VERSION 5.8 ;
BUSBITCHARS "[]" ;
DIVIDERCHAR "/" ;
UNITS
    DATABASE MICRONS 1000 ;
END UNITS

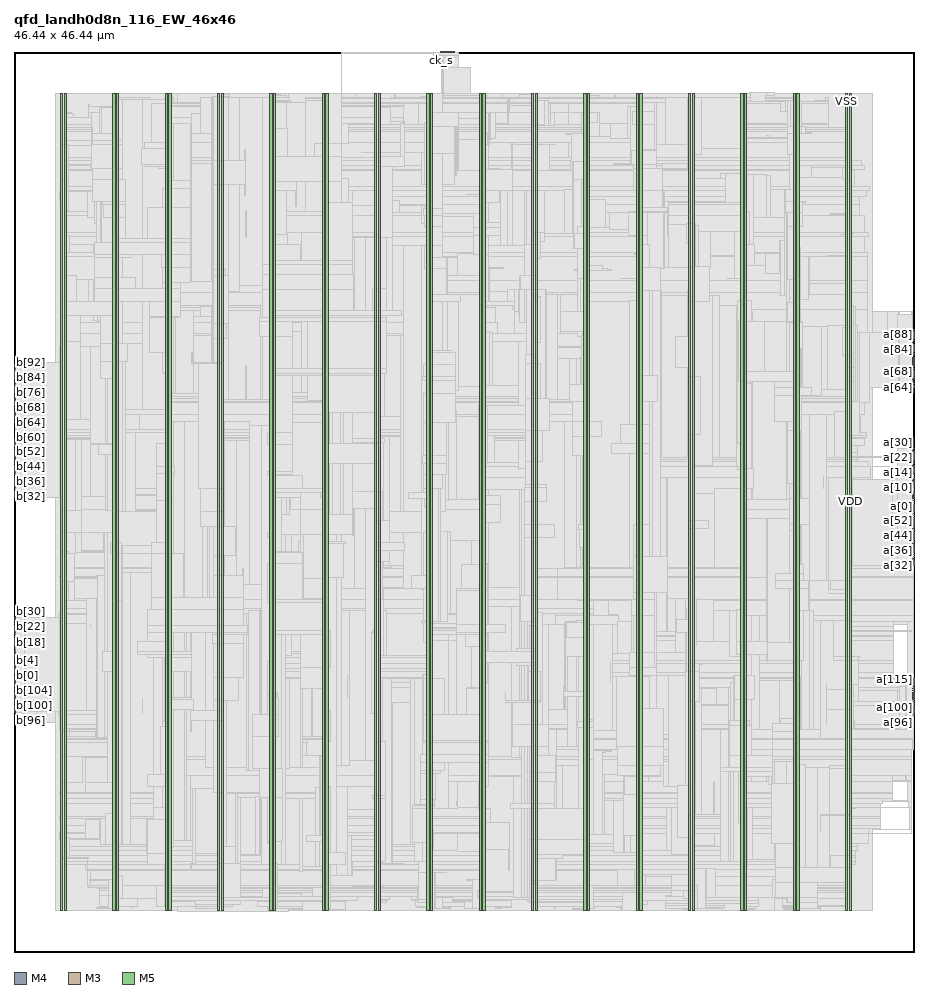
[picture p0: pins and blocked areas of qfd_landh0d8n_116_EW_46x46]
MACRO qfd_landh0d8n_116_EW_46x46
  FOREIGN qfd_landh0d8n_116_EW_46x46 0 0 ;
  CLASS BLOCK ;
  SIZE 46.44 BY 46.44 ;
  PIN a[0]
    DIRECTION INPUT ;
    USE SIGNAL ;
    PORT
      LAYER M4 ;
        RECT  46.356 22.992 46.44 23.016 ;
    END
  END a[0]
  PIN a[100]
    DIRECTION INPUT ;
    USE SIGNAL ;
    PORT
      LAYER M4 ;
        RECT  46.356 12.624 46.44 12.648 ;
    END
  END a[100]
  PIN a[101]
    DIRECTION INPUT ;
    USE SIGNAL ;
    PORT
      LAYER M4 ;
        RECT  46.356 12.72 46.44 12.744 ;
    END
  END a[101]
  PIN a[102]
    DIRECTION INPUT ;
    USE SIGNAL ;
    PORT
      LAYER M4 ;
        RECT  46.356 12.816 46.44 12.84 ;
    END
  END a[102]
  PIN a[103]
    DIRECTION INPUT ;
    USE SIGNAL ;
    PORT
      LAYER M4 ;
        RECT  46.356 12.912 46.44 12.936 ;
    END
  END a[103]
  PIN a[104]
    DIRECTION INPUT ;
    USE SIGNAL ;
    PORT
      LAYER M4 ;
        RECT  46.356 13.008 46.44 13.032 ;
    END
  END a[104]
  PIN a[105]
    DIRECTION INPUT ;
    USE SIGNAL ;
    PORT
      LAYER M4 ;
        RECT  46.356 13.104 46.44 13.128 ;
    END
  END a[105]
  PIN a[106]
    DIRECTION INPUT ;
    USE SIGNAL ;
    PORT
      LAYER M4 ;
        RECT  46.356 13.2 46.44 13.224 ;
    END
  END a[106]
  PIN a[107]
    DIRECTION INPUT ;
    USE SIGNAL ;
    PORT
      LAYER M4 ;
        RECT  46.356 13.296 46.44 13.32 ;
    END
  END a[107]
  PIN a[108]
    DIRECTION INPUT ;
    USE SIGNAL ;
    PORT
      LAYER M4 ;
        RECT  46.356 13.392 46.44 13.416 ;
    END
  END a[108]
  PIN a[109]
    DIRECTION INPUT ;
    USE SIGNAL ;
    PORT
      LAYER M4 ;
        RECT  46.356 13.488 46.44 13.512 ;
    END
  END a[109]
  PIN a[10]
    DIRECTION INPUT ;
    USE SIGNAL ;
    PORT
      LAYER M4 ;
        RECT  46.356 23.952 46.44 23.976 ;
    END
  END a[10]
  PIN a[110]
    DIRECTION INPUT ;
    USE SIGNAL ;
    PORT
      LAYER M4 ;
        RECT  46.356 13.584 46.44 13.608 ;
    END
  END a[110]
  PIN a[111]
    DIRECTION INPUT ;
    USE SIGNAL ;
    PORT
      LAYER M4 ;
        RECT  46.356 13.68 46.44 13.704 ;
    END
  END a[111]
  PIN a[112]
    DIRECTION INPUT ;
    USE SIGNAL ;
    PORT
      LAYER M4 ;
        RECT  46.356 13.776 46.44 13.8 ;
    END
  END a[112]
  PIN a[113]
    DIRECTION INPUT ;
    USE SIGNAL ;
    PORT
      LAYER M4 ;
        RECT  46.356 13.872 46.44 13.896 ;
    END
  END a[113]
  PIN a[114]
    DIRECTION INPUT ;
    USE SIGNAL ;
    PORT
      LAYER M4 ;
        RECT  46.356 13.968 46.44 13.992 ;
    END
  END a[114]
  PIN a[115]
    DIRECTION INPUT ;
    USE SIGNAL ;
    PORT
      LAYER M4 ;
        RECT  46.356 14.064 46.44 14.088 ;
    END
  END a[115]
  PIN a[11]
    DIRECTION INPUT ;
    USE SIGNAL ;
    PORT
      LAYER M4 ;
        RECT  46.356 24.048 46.44 24.072 ;
    END
  END a[11]
  PIN a[12]
    DIRECTION INPUT ;
    USE SIGNAL ;
    PORT
      LAYER M4 ;
        RECT  46.356 24.144 46.44 24.168 ;
    END
  END a[12]
  PIN a[13]
    DIRECTION INPUT ;
    USE SIGNAL ;
    PORT
      LAYER M4 ;
        RECT  46.356 24.24 46.44 24.264 ;
    END
  END a[13]
  PIN a[14]
    DIRECTION INPUT ;
    USE SIGNAL ;
    PORT
      LAYER M4 ;
        RECT  46.356 24.336 46.44 24.36 ;
    END
  END a[14]
  PIN a[15]
    DIRECTION INPUT ;
    USE SIGNAL ;
    PORT
      LAYER M4 ;
        RECT  46.356 24.432 46.44 24.456 ;
    END
  END a[15]
  PIN a[16]
    DIRECTION INPUT ;
    USE SIGNAL ;
    PORT
      LAYER M4 ;
        RECT  46.356 24.528 46.44 24.552 ;
    END
  END a[16]
  PIN a[17]
    DIRECTION INPUT ;
    USE SIGNAL ;
    PORT
      LAYER M4 ;
        RECT  46.356 24.624 46.44 24.648 ;
    END
  END a[17]
  PIN a[18]
    DIRECTION INPUT ;
    USE SIGNAL ;
    PORT
      LAYER M4 ;
        RECT  46.356 24.72 46.44 24.744 ;
    END
  END a[18]
  PIN a[19]
    DIRECTION INPUT ;
    USE SIGNAL ;
    PORT
      LAYER M4 ;
        RECT  46.356 24.816 46.44 24.84 ;
    END
  END a[19]
  PIN a[1]
    DIRECTION INPUT ;
    USE SIGNAL ;
    PORT
      LAYER M4 ;
        RECT  46.356 23.088 46.44 23.112 ;
    END
  END a[1]
  PIN a[20]
    DIRECTION INPUT ;
    USE SIGNAL ;
    PORT
      LAYER M4 ;
        RECT  46.356 24.912 46.44 24.936 ;
    END
  END a[20]
  PIN a[21]
    DIRECTION INPUT ;
    USE SIGNAL ;
    PORT
      LAYER M4 ;
        RECT  46.356 25.008 46.44 25.032 ;
    END
  END a[21]
  PIN a[22]
    DIRECTION INPUT ;
    USE SIGNAL ;
    PORT
      LAYER M4 ;
        RECT  46.356 25.104 46.44 25.128 ;
    END
  END a[22]
  PIN a[23]
    DIRECTION INPUT ;
    USE SIGNAL ;
    PORT
      LAYER M4 ;
        RECT  46.356 25.2 46.44 25.224 ;
    END
  END a[23]
  PIN a[24]
    DIRECTION INPUT ;
    USE SIGNAL ;
    PORT
      LAYER M4 ;
        RECT  46.356 25.296 46.44 25.32 ;
    END
  END a[24]
  PIN a[25]
    DIRECTION INPUT ;
    USE SIGNAL ;
    PORT
      LAYER M4 ;
        RECT  46.356 25.392 46.44 25.416 ;
    END
  END a[25]
  PIN a[26]
    DIRECTION INPUT ;
    USE SIGNAL ;
    PORT
      LAYER M4 ;
        RECT  46.356 25.488 46.44 25.512 ;
    END
  END a[26]
  PIN a[27]
    DIRECTION INPUT ;
    USE SIGNAL ;
    PORT
      LAYER M4 ;
        RECT  46.356 25.584 46.44 25.608 ;
    END
  END a[27]
  PIN a[28]
    DIRECTION INPUT ;
    USE SIGNAL ;
    PORT
      LAYER M4 ;
        RECT  46.356 25.68 46.44 25.704 ;
    END
  END a[28]
  PIN a[29]
    DIRECTION INPUT ;
    USE SIGNAL ;
    PORT
      LAYER M4 ;
        RECT  46.356 25.776 46.44 25.8 ;
    END
  END a[29]
  PIN a[2]
    DIRECTION INPUT ;
    USE SIGNAL ;
    PORT
      LAYER M4 ;
        RECT  46.356 23.184 46.44 23.208 ;
    END
  END a[2]
  PIN a[30]
    DIRECTION INPUT ;
    USE SIGNAL ;
    PORT
      LAYER M4 ;
        RECT  46.356 25.872 46.44 25.896 ;
    END
  END a[30]
  PIN a[31]
    DIRECTION INPUT ;
    USE SIGNAL ;
    PORT
      LAYER M4 ;
        RECT  46.356 25.968 46.44 25.992 ;
    END
  END a[31]
  PIN a[32]
    DIRECTION INPUT ;
    USE SIGNAL ;
    PORT
      LAYER M4 ;
        RECT  46.356 19.92 46.44 19.944 ;
    END
  END a[32]
  PIN a[33]
    DIRECTION INPUT ;
    USE SIGNAL ;
    PORT
      LAYER M4 ;
        RECT  46.356 20.016 46.44 20.04 ;
    END
  END a[33]
  PIN a[34]
    DIRECTION INPUT ;
    USE SIGNAL ;
    PORT
      LAYER M4 ;
        RECT  46.356 20.112 46.44 20.136 ;
    END
  END a[34]
  PIN a[35]
    DIRECTION INPUT ;
    USE SIGNAL ;
    PORT
      LAYER M4 ;
        RECT  46.356 20.208 46.44 20.232 ;
    END
  END a[35]
  PIN a[36]
    DIRECTION INPUT ;
    USE SIGNAL ;
    PORT
      LAYER M4 ;
        RECT  46.356 20.304 46.44 20.328 ;
    END
  END a[36]
  PIN a[37]
    DIRECTION INPUT ;
    USE SIGNAL ;
    PORT
      LAYER M4 ;
        RECT  46.356 20.4 46.44 20.424 ;
    END
  END a[37]
  PIN a[38]
    DIRECTION INPUT ;
    USE SIGNAL ;
    PORT
      LAYER M4 ;
        RECT  46.356 20.496 46.44 20.52 ;
    END
  END a[38]
  PIN a[39]
    DIRECTION INPUT ;
    USE SIGNAL ;
    PORT
      LAYER M4 ;
        RECT  46.356 20.592 46.44 20.616 ;
    END
  END a[39]
  PIN a[3]
    DIRECTION INPUT ;
    USE SIGNAL ;
    PORT
      LAYER M4 ;
        RECT  46.356 23.28 46.44 23.304 ;
    END
  END a[3]
  PIN a[40]
    DIRECTION INPUT ;
    USE SIGNAL ;
    PORT
      LAYER M4 ;
        RECT  46.356 20.688 46.44 20.712 ;
    END
  END a[40]
  PIN a[41]
    DIRECTION INPUT ;
    USE SIGNAL ;
    PORT
      LAYER M4 ;
        RECT  46.356 20.784 46.44 20.808 ;
    END
  END a[41]
  PIN a[42]
    DIRECTION INPUT ;
    USE SIGNAL ;
    PORT
      LAYER M4 ;
        RECT  46.356 20.88 46.44 20.904 ;
    END
  END a[42]
  PIN a[43]
    DIRECTION INPUT ;
    USE SIGNAL ;
    PORT
      LAYER M4 ;
        RECT  46.356 20.976 46.44 21 ;
    END
  END a[43]
  PIN a[44]
    DIRECTION INPUT ;
    USE SIGNAL ;
    PORT
      LAYER M4 ;
        RECT  46.356 21.072 46.44 21.096 ;
    END
  END a[44]
  PIN a[45]
    DIRECTION INPUT ;
    USE SIGNAL ;
    PORT
      LAYER M4 ;
        RECT  46.356 21.168 46.44 21.192 ;
    END
  END a[45]
  PIN a[46]
    DIRECTION INPUT ;
    USE SIGNAL ;
    PORT
      LAYER M4 ;
        RECT  46.356 21.264 46.44 21.288 ;
    END
  END a[46]
  PIN a[47]
    DIRECTION INPUT ;
    USE SIGNAL ;
    PORT
      LAYER M4 ;
        RECT  46.356 21.36 46.44 21.384 ;
    END
  END a[47]
  PIN a[48]
    DIRECTION INPUT ;
    USE SIGNAL ;
    PORT
      LAYER M4 ;
        RECT  46.356 21.456 46.44 21.48 ;
    END
  END a[48]
  PIN a[49]
    DIRECTION INPUT ;
    USE SIGNAL ;
    PORT
      LAYER M4 ;
        RECT  46.356 21.552 46.44 21.576 ;
    END
  END a[49]
  PIN a[4]
    DIRECTION INPUT ;
    USE SIGNAL ;
    PORT
      LAYER M4 ;
        RECT  46.356 23.376 46.44 23.4 ;
    END
  END a[4]
  PIN a[50]
    DIRECTION INPUT ;
    USE SIGNAL ;
    PORT
      LAYER M4 ;
        RECT  46.356 21.648 46.44 21.672 ;
    END
  END a[50]
  PIN a[51]
    DIRECTION INPUT ;
    USE SIGNAL ;
    PORT
      LAYER M4 ;
        RECT  46.356 21.744 46.44 21.768 ;
    END
  END a[51]
  PIN a[52]
    DIRECTION INPUT ;
    USE SIGNAL ;
    PORT
      LAYER M4 ;
        RECT  46.356 21.84 46.44 21.864 ;
    END
  END a[52]
  PIN a[53]
    DIRECTION INPUT ;
    USE SIGNAL ;
    PORT
      LAYER M4 ;
        RECT  46.356 21.936 46.44 21.96 ;
    END
  END a[53]
  PIN a[54]
    DIRECTION INPUT ;
    USE SIGNAL ;
    PORT
      LAYER M4 ;
        RECT  46.356 22.032 46.44 22.056 ;
    END
  END a[54]
  PIN a[55]
    DIRECTION INPUT ;
    USE SIGNAL ;
    PORT
      LAYER M4 ;
        RECT  46.356 22.128 46.44 22.152 ;
    END
  END a[55]
  PIN a[56]
    DIRECTION INPUT ;
    USE SIGNAL ;
    PORT
      LAYER M4 ;
        RECT  46.356 22.224 46.44 22.248 ;
    END
  END a[56]
  PIN a[57]
    DIRECTION INPUT ;
    USE SIGNAL ;
    PORT
      LAYER M4 ;
        RECT  46.356 22.32 46.44 22.344 ;
    END
  END a[57]
  PIN a[58]
    DIRECTION INPUT ;
    USE SIGNAL ;
    PORT
      LAYER M4 ;
        RECT  46.356 22.416 46.44 22.44 ;
    END
  END a[58]
  PIN a[59]
    DIRECTION INPUT ;
    USE SIGNAL ;
    PORT
      LAYER M4 ;
        RECT  46.356 22.512 46.44 22.536 ;
    END
  END a[59]
  PIN a[5]
    DIRECTION INPUT ;
    USE SIGNAL ;
    PORT
      LAYER M4 ;
        RECT  46.356 23.472 46.44 23.496 ;
    END
  END a[5]
  PIN a[60]
    DIRECTION INPUT ;
    USE SIGNAL ;
    PORT
      LAYER M4 ;
        RECT  46.356 22.608 46.44 22.632 ;
    END
  END a[60]
  PIN a[61]
    DIRECTION INPUT ;
    USE SIGNAL ;
    PORT
      LAYER M4 ;
        RECT  46.356 22.704 46.44 22.728 ;
    END
  END a[61]
  PIN a[62]
    DIRECTION INPUT ;
    USE SIGNAL ;
    PORT
      LAYER M4 ;
        RECT  46.356 22.8 46.44 22.824 ;
    END
  END a[62]
  PIN a[63]
    DIRECTION INPUT ;
    USE SIGNAL ;
    PORT
      LAYER M4 ;
        RECT  46.356 22.896 46.44 22.92 ;
    END
  END a[63]
  PIN a[64]
    DIRECTION INPUT ;
    USE SIGNAL ;
    PORT
      LAYER M4 ;
        RECT  46.356 29.136 46.44 29.16 ;
    END
  END a[64]
  PIN a[65]
    DIRECTION INPUT ;
    USE SIGNAL ;
    PORT
      LAYER M4 ;
        RECT  46.356 29.232 46.44 29.256 ;
    END
  END a[65]
  PIN a[66]
    DIRECTION INPUT ;
    USE SIGNAL ;
    PORT
      LAYER M4 ;
        RECT  46.356 29.328 46.44 29.352 ;
    END
  END a[66]
  PIN a[67]
    DIRECTION INPUT ;
    USE SIGNAL ;
    PORT
      LAYER M4 ;
        RECT  46.356 29.424 46.44 29.448 ;
    END
  END a[67]
  PIN a[68]
    DIRECTION INPUT ;
    USE SIGNAL ;
    PORT
      LAYER M4 ;
        RECT  46.356 29.52 46.44 29.544 ;
    END
  END a[68]
  PIN a[69]
    DIRECTION INPUT ;
    USE SIGNAL ;
    PORT
      LAYER M4 ;
        RECT  46.356 29.616 46.44 29.64 ;
    END
  END a[69]
  PIN a[6]
    DIRECTION INPUT ;
    USE SIGNAL ;
    PORT
      LAYER M4 ;
        RECT  46.356 23.568 46.44 23.592 ;
    END
  END a[6]
  PIN a[70]
    DIRECTION INPUT ;
    USE SIGNAL ;
    PORT
      LAYER M4 ;
        RECT  46.356 29.712 46.44 29.736 ;
    END
  END a[70]
  PIN a[71]
    DIRECTION INPUT ;
    USE SIGNAL ;
    PORT
      LAYER M4 ;
        RECT  46.356 29.808 46.44 29.832 ;
    END
  END a[71]
  PIN a[72]
    DIRECTION INPUT ;
    USE SIGNAL ;
    PORT
      LAYER M4 ;
        RECT  46.356 29.904 46.44 29.928 ;
    END
  END a[72]
  PIN a[73]
    DIRECTION INPUT ;
    USE SIGNAL ;
    PORT
      LAYER M4 ;
        RECT  46.356 30 46.44 30.024 ;
    END
  END a[73]
  PIN a[74]
    DIRECTION INPUT ;
    USE SIGNAL ;
    PORT
      LAYER M4 ;
        RECT  46.356 30.096 46.44 30.12 ;
    END
  END a[74]
  PIN a[75]
    DIRECTION INPUT ;
    USE SIGNAL ;
    PORT
      LAYER M4 ;
        RECT  46.356 30.192 46.44 30.216 ;
    END
  END a[75]
  PIN a[76]
    DIRECTION INPUT ;
    USE SIGNAL ;
    PORT
      LAYER M4 ;
        RECT  46.356 30.288 46.44 30.312 ;
    END
  END a[76]
  PIN a[77]
    DIRECTION INPUT ;
    USE SIGNAL ;
    PORT
      LAYER M4 ;
        RECT  46.356 30.384 46.44 30.408 ;
    END
  END a[77]
  PIN a[78]
    DIRECTION INPUT ;
    USE SIGNAL ;
    PORT
      LAYER M4 ;
        RECT  46.356 30.48 46.44 30.504 ;
    END
  END a[78]
  PIN a[79]
    DIRECTION INPUT ;
    USE SIGNAL ;
    PORT
      LAYER M4 ;
        RECT  46.356 30.576 46.44 30.6 ;
    END
  END a[79]
  PIN a[7]
    DIRECTION INPUT ;
    USE SIGNAL ;
    PORT
      LAYER M4 ;
        RECT  46.356 23.664 46.44 23.688 ;
    END
  END a[7]
  PIN a[80]
    DIRECTION INPUT ;
    USE SIGNAL ;
    PORT
      LAYER M4 ;
        RECT  46.356 30.672 46.44 30.696 ;
    END
  END a[80]
  PIN a[81]
    DIRECTION INPUT ;
    USE SIGNAL ;
    PORT
      LAYER M4 ;
        RECT  46.356 30.768 46.44 30.792 ;
    END
  END a[81]
  PIN a[82]
    DIRECTION INPUT ;
    USE SIGNAL ;
    PORT
      LAYER M4 ;
        RECT  46.356 30.864 46.44 30.888 ;
    END
  END a[82]
  PIN a[83]
    DIRECTION INPUT ;
    USE SIGNAL ;
    PORT
      LAYER M4 ;
        RECT  46.356 30.96 46.44 30.984 ;
    END
  END a[83]
  PIN a[84]
    DIRECTION INPUT ;
    USE SIGNAL ;
    PORT
      LAYER M4 ;
        RECT  46.356 31.056 46.44 31.08 ;
    END
  END a[84]
  PIN a[85]
    DIRECTION INPUT ;
    USE SIGNAL ;
    PORT
      LAYER M4 ;
        RECT  46.356 31.152 46.44 31.176 ;
    END
  END a[85]
  PIN a[86]
    DIRECTION INPUT ;
    USE SIGNAL ;
    PORT
      LAYER M4 ;
        RECT  46.356 31.248 46.44 31.272 ;
    END
  END a[86]
  PIN a[87]
    DIRECTION INPUT ;
    USE SIGNAL ;
    PORT
      LAYER M4 ;
        RECT  46.356 31.344 46.44 31.368 ;
    END
  END a[87]
  PIN a[88]
    DIRECTION INPUT ;
    USE SIGNAL ;
    PORT
      LAYER M4 ;
        RECT  46.356 31.44 46.44 31.464 ;
    END
  END a[88]
  PIN a[89]
    DIRECTION INPUT ;
    USE SIGNAL ;
    PORT
      LAYER M4 ;
        RECT  46.356 31.536 46.44 31.56 ;
    END
  END a[89]
  PIN a[8]
    DIRECTION INPUT ;
    USE SIGNAL ;
    PORT
      LAYER M4 ;
        RECT  46.356 23.76 46.44 23.784 ;
    END
  END a[8]
  PIN a[90]
    DIRECTION INPUT ;
    USE SIGNAL ;
    PORT
      LAYER M4 ;
        RECT  46.356 31.632 46.44 31.656 ;
    END
  END a[90]
  PIN a[91]
    DIRECTION INPUT ;
    USE SIGNAL ;
    PORT
      LAYER M4 ;
        RECT  46.356 31.728 46.44 31.752 ;
    END
  END a[91]
  PIN a[92]
    DIRECTION INPUT ;
    USE SIGNAL ;
    PORT
      LAYER M4 ;
        RECT  46.356 31.824 46.44 31.848 ;
    END
  END a[92]
  PIN a[93]
    DIRECTION INPUT ;
    USE SIGNAL ;
    PORT
      LAYER M4 ;
        RECT  46.356 31.92 46.44 31.944 ;
    END
  END a[93]
  PIN a[94]
    DIRECTION INPUT ;
    USE SIGNAL ;
    PORT
      LAYER M4 ;
        RECT  46.356 32.016 46.44 32.04 ;
    END
  END a[94]
  PIN a[95]
    DIRECTION INPUT ;
    USE SIGNAL ;
    PORT
      LAYER M4 ;
        RECT  46.356 32.112 46.44 32.136 ;
    END
  END a[95]
  PIN a[96]
    DIRECTION INPUT ;
    USE SIGNAL ;
    PORT
      LAYER M4 ;
        RECT  46.356 12.24 46.44 12.264 ;
    END
  END a[96]
  PIN a[97]
    DIRECTION INPUT ;
    USE SIGNAL ;
    PORT
      LAYER M4 ;
        RECT  46.356 12.336 46.44 12.36 ;
    END
  END a[97]
  PIN a[98]
    DIRECTION INPUT ;
    USE SIGNAL ;
    PORT
      LAYER M4 ;
        RECT  46.356 12.432 46.44 12.456 ;
    END
  END a[98]
  PIN a[99]
    DIRECTION INPUT ;
    USE SIGNAL ;
    PORT
      LAYER M4 ;
        RECT  46.356 12.528 46.44 12.552 ;
    END
  END a[99]
  PIN a[9]
    DIRECTION INPUT ;
    USE SIGNAL ;
    PORT
      LAYER M4 ;
        RECT  46.356 23.856 46.44 23.88 ;
    END
  END a[9]
  PIN b[0]
    DIRECTION OUTPUT ;
    USE SIGNAL ;
    PORT
      LAYER M4 ;
        RECT  0 14.256 0.084 14.28 ;
    END
  END b[0]
  PIN b[100]
    DIRECTION OUTPUT ;
    USE SIGNAL ;
    PORT
      LAYER M4 ;
        RECT  0 12.72 0.084 12.744 ;
    END
  END b[100]
  PIN b[101]
    DIRECTION OUTPUT ;
    USE SIGNAL ;
    PORT
      LAYER M4 ;
        RECT  0 12.816 0.084 12.84 ;
    END
  END b[101]
  PIN b[102]
    DIRECTION OUTPUT ;
    USE SIGNAL ;
    PORT
      LAYER M4 ;
        RECT  0 12.912 0.084 12.936 ;
    END
  END b[102]
  PIN b[103]
    DIRECTION OUTPUT ;
    USE SIGNAL ;
    PORT
      LAYER M4 ;
        RECT  0 13.008 0.084 13.032 ;
    END
  END b[103]
  PIN b[104]
    DIRECTION OUTPUT ;
    USE SIGNAL ;
    PORT
      LAYER M4 ;
        RECT  0 13.104 0.084 13.128 ;
    END
  END b[104]
  PIN b[105]
    DIRECTION OUTPUT ;
    USE SIGNAL ;
    PORT
      LAYER M4 ;
        RECT  0 13.2 0.084 13.224 ;
    END
  END b[105]
  PIN b[106]
    DIRECTION OUTPUT ;
    USE SIGNAL ;
    PORT
      LAYER M4 ;
        RECT  0 13.296 0.084 13.32 ;
    END
  END b[106]
  PIN b[107]
    DIRECTION OUTPUT ;
    USE SIGNAL ;
    PORT
      LAYER M4 ;
        RECT  0 13.392 0.084 13.416 ;
    END
  END b[107]
  PIN b[108]
    DIRECTION OUTPUT ;
    USE SIGNAL ;
    PORT
      LAYER M4 ;
        RECT  0 13.488 0.084 13.512 ;
    END
  END b[108]
  PIN b[109]
    DIRECTION OUTPUT ;
    USE SIGNAL ;
    PORT
      LAYER M4 ;
        RECT  0 13.584 0.084 13.608 ;
    END
  END b[109]
  PIN b[10]
    DIRECTION OUTPUT ;
    USE SIGNAL ;
    PORT
      LAYER M4 ;
        RECT  0 15.216 0.084 15.24 ;
    END
  END b[10]
  PIN b[110]
    DIRECTION OUTPUT ;
    USE SIGNAL ;
    PORT
      LAYER M4 ;
        RECT  0 13.68 0.084 13.704 ;
    END
  END b[110]
  PIN b[111]
    DIRECTION OUTPUT ;
    USE SIGNAL ;
    PORT
      LAYER M4 ;
        RECT  0 13.776 0.084 13.8 ;
    END
  END b[111]
  PIN b[112]
    DIRECTION OUTPUT ;
    USE SIGNAL ;
    PORT
      LAYER M4 ;
        RECT  0 13.872 0.084 13.896 ;
    END
  END b[112]
  PIN b[113]
    DIRECTION OUTPUT ;
    USE SIGNAL ;
    PORT
      LAYER M4 ;
        RECT  0 13.968 0.084 13.992 ;
    END
  END b[113]
  PIN b[114]
    DIRECTION OUTPUT ;
    USE SIGNAL ;
    PORT
      LAYER M4 ;
        RECT  0 14.064 0.084 14.088 ;
    END
  END b[114]
  PIN b[115]
    DIRECTION OUTPUT ;
    USE SIGNAL ;
    PORT
      LAYER M4 ;
        RECT  0 14.16 0.084 14.184 ;
    END
  END b[115]
  PIN b[11]
    DIRECTION OUTPUT ;
    USE SIGNAL ;
    PORT
      LAYER M4 ;
        RECT  0 15.312 0.084 15.336 ;
    END
  END b[11]
  PIN b[12]
    DIRECTION OUTPUT ;
    USE SIGNAL ;
    PORT
      LAYER M4 ;
        RECT  0 15.408 0.084 15.432 ;
    END
  END b[12]
  PIN b[13]
    DIRECTION OUTPUT ;
    USE SIGNAL ;
    PORT
      LAYER M4 ;
        RECT  0 15.504 0.084 15.528 ;
    END
  END b[13]
  PIN b[14]
    DIRECTION OUTPUT ;
    USE SIGNAL ;
    PORT
      LAYER M4 ;
        RECT  0 15.6 0.084 15.624 ;
    END
  END b[14]
  PIN b[15]
    DIRECTION OUTPUT ;
    USE SIGNAL ;
    PORT
      LAYER M4 ;
        RECT  0 15.696 0.084 15.72 ;
    END
  END b[15]
  PIN b[16]
    DIRECTION OUTPUT ;
    USE SIGNAL ;
    PORT
      LAYER M4 ;
        RECT  0 15.792 0.084 15.816 ;
    END
  END b[16]
  PIN b[17]
    DIRECTION OUTPUT ;
    USE SIGNAL ;
    PORT
      LAYER M4 ;
        RECT  0 15.888 0.084 15.912 ;
    END
  END b[17]
  PIN b[18]
    DIRECTION OUTPUT ;
    USE SIGNAL ;
    PORT
      LAYER M4 ;
        RECT  0 15.984 0.084 16.008 ;
    END
  END b[18]
  PIN b[19]
    DIRECTION OUTPUT ;
    USE SIGNAL ;
    PORT
      LAYER M4 ;
        RECT  0 16.08 0.084 16.104 ;
    END
  END b[19]
  PIN b[1]
    DIRECTION OUTPUT ;
    USE SIGNAL ;
    PORT
      LAYER M4 ;
        RECT  0 14.352 0.084 14.376 ;
    END
  END b[1]
  PIN b[20]
    DIRECTION OUTPUT ;
    USE SIGNAL ;
    PORT
      LAYER M4 ;
        RECT  0 16.176 0.084 16.2 ;
    END
  END b[20]
  PIN b[21]
    DIRECTION OUTPUT ;
    USE SIGNAL ;
    PORT
      LAYER M4 ;
        RECT  0 16.272 0.084 16.296 ;
    END
  END b[21]
  PIN b[22]
    DIRECTION OUTPUT ;
    USE SIGNAL ;
    PORT
      LAYER M4 ;
        RECT  0 16.368 0.084 16.392 ;
    END
  END b[22]
  PIN b[23]
    DIRECTION OUTPUT ;
    USE SIGNAL ;
    PORT
      LAYER M4 ;
        RECT  0 16.464 0.084 16.488 ;
    END
  END b[23]
  PIN b[24]
    DIRECTION OUTPUT ;
    USE SIGNAL ;
    PORT
      LAYER M4 ;
        RECT  0 16.56 0.084 16.584 ;
    END
  END b[24]
  PIN b[25]
    DIRECTION OUTPUT ;
    USE SIGNAL ;
    PORT
      LAYER M4 ;
        RECT  0 16.656 0.084 16.68 ;
    END
  END b[25]
  PIN b[26]
    DIRECTION OUTPUT ;
    USE SIGNAL ;
    PORT
      LAYER M4 ;
        RECT  0 16.752 0.084 16.776 ;
    END
  END b[26]
  PIN b[27]
    DIRECTION OUTPUT ;
    USE SIGNAL ;
    PORT
      LAYER M4 ;
        RECT  0 16.848 0.084 16.872 ;
    END
  END b[27]
  PIN b[28]
    DIRECTION OUTPUT ;
    USE SIGNAL ;
    PORT
      LAYER M4 ;
        RECT  0 16.944 0.084 16.968 ;
    END
  END b[28]
  PIN b[29]
    DIRECTION OUTPUT ;
    USE SIGNAL ;
    PORT
      LAYER M4 ;
        RECT  0 17.04 0.084 17.064 ;
    END
  END b[29]
  PIN b[2]
    DIRECTION OUTPUT ;
    USE SIGNAL ;
    PORT
      LAYER M4 ;
        RECT  0 14.448 0.084 14.472 ;
    END
  END b[2]
  PIN b[30]
    DIRECTION OUTPUT ;
    USE SIGNAL ;
    PORT
      LAYER M4 ;
        RECT  0 17.136 0.084 17.16 ;
    END
  END b[30]
  PIN b[31]
    DIRECTION OUTPUT ;
    USE SIGNAL ;
    PORT
      LAYER M4 ;
        RECT  0 17.232 0.084 17.256 ;
    END
  END b[31]
  PIN b[32]
    DIRECTION OUTPUT ;
    USE SIGNAL ;
    PORT
      LAYER M4 ;
        RECT  0 23.472 0.084 23.496 ;
    END
  END b[32]
  PIN b[33]
    DIRECTION OUTPUT ;
    USE SIGNAL ;
    PORT
      LAYER M4 ;
        RECT  0 23.568 0.084 23.592 ;
    END
  END b[33]
  PIN b[34]
    DIRECTION OUTPUT ;
    USE SIGNAL ;
    PORT
      LAYER M4 ;
        RECT  0 23.664 0.084 23.688 ;
    END
  END b[34]
  PIN b[35]
    DIRECTION OUTPUT ;
    USE SIGNAL ;
    PORT
      LAYER M4 ;
        RECT  0 23.76 0.084 23.784 ;
    END
  END b[35]
  PIN b[36]
    DIRECTION OUTPUT ;
    USE SIGNAL ;
    PORT
      LAYER M4 ;
        RECT  0 23.856 0.084 23.88 ;
    END
  END b[36]
  PIN b[37]
    DIRECTION OUTPUT ;
    USE SIGNAL ;
    PORT
      LAYER M4 ;
        RECT  0 23.952 0.084 23.976 ;
    END
  END b[37]
  PIN b[38]
    DIRECTION OUTPUT ;
    USE SIGNAL ;
    PORT
      LAYER M4 ;
        RECT  0 24.048 0.084 24.072 ;
    END
  END b[38]
  PIN b[39]
    DIRECTION OUTPUT ;
    USE SIGNAL ;
    PORT
      LAYER M4 ;
        RECT  0 24.144 0.084 24.168 ;
    END
  END b[39]
  PIN b[3]
    DIRECTION OUTPUT ;
    USE SIGNAL ;
    PORT
      LAYER M4 ;
        RECT  0 14.544 0.084 14.568 ;
    END
  END b[3]
  PIN b[40]
    DIRECTION OUTPUT ;
    USE SIGNAL ;
    PORT
      LAYER M4 ;
        RECT  0 24.24 0.084 24.264 ;
    END
  END b[40]
  PIN b[41]
    DIRECTION OUTPUT ;
    USE SIGNAL ;
    PORT
      LAYER M4 ;
        RECT  0 24.336 0.084 24.36 ;
    END
  END b[41]
  PIN b[42]
    DIRECTION OUTPUT ;
    USE SIGNAL ;
    PORT
      LAYER M4 ;
        RECT  0 24.432 0.084 24.456 ;
    END
  END b[42]
  PIN b[43]
    DIRECTION OUTPUT ;
    USE SIGNAL ;
    PORT
      LAYER M4 ;
        RECT  0 24.528 0.084 24.552 ;
    END
  END b[43]
  PIN b[44]
    DIRECTION OUTPUT ;
    USE SIGNAL ;
    PORT
      LAYER M4 ;
        RECT  0 24.624 0.084 24.648 ;
    END
  END b[44]
  PIN b[45]
    DIRECTION OUTPUT ;
    USE SIGNAL ;
    PORT
      LAYER M4 ;
        RECT  0 24.72 0.084 24.744 ;
    END
  END b[45]
  PIN b[46]
    DIRECTION OUTPUT ;
    USE SIGNAL ;
    PORT
      LAYER M4 ;
        RECT  0 24.816 0.084 24.84 ;
    END
  END b[46]
  PIN b[47]
    DIRECTION OUTPUT ;
    USE SIGNAL ;
    PORT
      LAYER M4 ;
        RECT  0 24.912 0.084 24.936 ;
    END
  END b[47]
  PIN b[48]
    DIRECTION OUTPUT ;
    USE SIGNAL ;
    PORT
      LAYER M4 ;
        RECT  0 25.008 0.084 25.032 ;
    END
  END b[48]
  PIN b[49]
    DIRECTION OUTPUT ;
    USE SIGNAL ;
    PORT
      LAYER M4 ;
        RECT  0 25.104 0.084 25.128 ;
    END
  END b[49]
  PIN b[4]
    DIRECTION OUTPUT ;
    USE SIGNAL ;
    PORT
      LAYER M4 ;
        RECT  0 14.64 0.084 14.664 ;
    END
  END b[4]
  PIN b[50]
    DIRECTION OUTPUT ;
    USE SIGNAL ;
    PORT
      LAYER M4 ;
        RECT  0 25.2 0.084 25.224 ;
    END
  END b[50]
  PIN b[51]
    DIRECTION OUTPUT ;
    USE SIGNAL ;
    PORT
      LAYER M4 ;
        RECT  0 25.296 0.084 25.32 ;
    END
  END b[51]
  PIN b[52]
    DIRECTION OUTPUT ;
    USE SIGNAL ;
    PORT
      LAYER M4 ;
        RECT  0 25.392 0.084 25.416 ;
    END
  END b[52]
  PIN b[53]
    DIRECTION OUTPUT ;
    USE SIGNAL ;
    PORT
      LAYER M4 ;
        RECT  0 25.488 0.084 25.512 ;
    END
  END b[53]
  PIN b[54]
    DIRECTION OUTPUT ;
    USE SIGNAL ;
    PORT
      LAYER M4 ;
        RECT  0 25.584 0.084 25.608 ;
    END
  END b[54]
  PIN b[55]
    DIRECTION OUTPUT ;
    USE SIGNAL ;
    PORT
      LAYER M4 ;
        RECT  0 25.68 0.084 25.704 ;
    END
  END b[55]
  PIN b[56]
    DIRECTION OUTPUT ;
    USE SIGNAL ;
    PORT
      LAYER M4 ;
        RECT  0 25.776 0.084 25.8 ;
    END
  END b[56]
  PIN b[57]
    DIRECTION OUTPUT ;
    USE SIGNAL ;
    PORT
      LAYER M4 ;
        RECT  0 25.872 0.084 25.896 ;
    END
  END b[57]
  PIN b[58]
    DIRECTION OUTPUT ;
    USE SIGNAL ;
    PORT
      LAYER M4 ;
        RECT  0 25.968 0.084 25.992 ;
    END
  END b[58]
  PIN b[59]
    DIRECTION OUTPUT ;
    USE SIGNAL ;
    PORT
      LAYER M4 ;
        RECT  0 26.064 0.084 26.088 ;
    END
  END b[59]
  PIN b[5]
    DIRECTION OUTPUT ;
    USE SIGNAL ;
    PORT
      LAYER M4 ;
        RECT  0 14.736 0.084 14.76 ;
    END
  END b[5]
  PIN b[60]
    DIRECTION OUTPUT ;
    USE SIGNAL ;
    PORT
      LAYER M4 ;
        RECT  0 26.16 0.084 26.184 ;
    END
  END b[60]
  PIN b[61]
    DIRECTION OUTPUT ;
    USE SIGNAL ;
    PORT
      LAYER M4 ;
        RECT  0 26.256 0.084 26.28 ;
    END
  END b[61]
  PIN b[62]
    DIRECTION OUTPUT ;
    USE SIGNAL ;
    PORT
      LAYER M4 ;
        RECT  0 26.352 0.084 26.376 ;
    END
  END b[62]
  PIN b[63]
    DIRECTION OUTPUT ;
    USE SIGNAL ;
    PORT
      LAYER M4 ;
        RECT  0 26.448 0.084 26.472 ;
    END
  END b[63]
  PIN b[64]
    DIRECTION OUTPUT ;
    USE SIGNAL ;
    PORT
      LAYER M4 ;
        RECT  0 27.312 0.084 27.336 ;
    END
  END b[64]
  PIN b[65]
    DIRECTION OUTPUT ;
    USE SIGNAL ;
    PORT
      LAYER M4 ;
        RECT  0 27.408 0.084 27.432 ;
    END
  END b[65]
  PIN b[66]
    DIRECTION OUTPUT ;
    USE SIGNAL ;
    PORT
      LAYER M4 ;
        RECT  0 27.504 0.084 27.528 ;
    END
  END b[66]
  PIN b[67]
    DIRECTION OUTPUT ;
    USE SIGNAL ;
    PORT
      LAYER M4 ;
        RECT  0 27.6 0.084 27.624 ;
    END
  END b[67]
  PIN b[68]
    DIRECTION OUTPUT ;
    USE SIGNAL ;
    PORT
      LAYER M4 ;
        RECT  0 27.696 0.084 27.72 ;
    END
  END b[68]
  PIN b[69]
    DIRECTION OUTPUT ;
    USE SIGNAL ;
    PORT
      LAYER M4 ;
        RECT  0 27.792 0.084 27.816 ;
    END
  END b[69]
  PIN b[6]
    DIRECTION OUTPUT ;
    USE SIGNAL ;
    PORT
      LAYER M4 ;
        RECT  0 14.832 0.084 14.856 ;
    END
  END b[6]
  PIN b[70]
    DIRECTION OUTPUT ;
    USE SIGNAL ;
    PORT
      LAYER M4 ;
        RECT  0 27.888 0.084 27.912 ;
    END
  END b[70]
  PIN b[71]
    DIRECTION OUTPUT ;
    USE SIGNAL ;
    PORT
      LAYER M4 ;
        RECT  0 27.984 0.084 28.008 ;
    END
  END b[71]
  PIN b[72]
    DIRECTION OUTPUT ;
    USE SIGNAL ;
    PORT
      LAYER M4 ;
        RECT  0 28.08 0.084 28.104 ;
    END
  END b[72]
  PIN b[73]
    DIRECTION OUTPUT ;
    USE SIGNAL ;
    PORT
      LAYER M4 ;
        RECT  0 28.176 0.084 28.2 ;
    END
  END b[73]
  PIN b[74]
    DIRECTION OUTPUT ;
    USE SIGNAL ;
    PORT
      LAYER M4 ;
        RECT  0 28.272 0.084 28.296 ;
    END
  END b[74]
  PIN b[75]
    DIRECTION OUTPUT ;
    USE SIGNAL ;
    PORT
      LAYER M4 ;
        RECT  0 28.368 0.084 28.392 ;
    END
  END b[75]
  PIN b[76]
    DIRECTION OUTPUT ;
    USE SIGNAL ;
    PORT
      LAYER M4 ;
        RECT  0 28.464 0.084 28.488 ;
    END
  END b[76]
  PIN b[77]
    DIRECTION OUTPUT ;
    USE SIGNAL ;
    PORT
      LAYER M4 ;
        RECT  0 28.56 0.084 28.584 ;
    END
  END b[77]
  PIN b[78]
    DIRECTION OUTPUT ;
    USE SIGNAL ;
    PORT
      LAYER M4 ;
        RECT  0 28.656 0.084 28.68 ;
    END
  END b[78]
  PIN b[79]
    DIRECTION OUTPUT ;
    USE SIGNAL ;
    PORT
      LAYER M4 ;
        RECT  0 28.752 0.084 28.776 ;
    END
  END b[79]
  PIN b[7]
    DIRECTION OUTPUT ;
    USE SIGNAL ;
    PORT
      LAYER M4 ;
        RECT  0 14.928 0.084 14.952 ;
    END
  END b[7]
  PIN b[80]
    DIRECTION OUTPUT ;
    USE SIGNAL ;
    PORT
      LAYER M4 ;
        RECT  0 28.848 0.084 28.872 ;
    END
  END b[80]
  PIN b[81]
    DIRECTION OUTPUT ;
    USE SIGNAL ;
    PORT
      LAYER M4 ;
        RECT  0 28.944 0.084 28.968 ;
    END
  END b[81]
  PIN b[82]
    DIRECTION OUTPUT ;
    USE SIGNAL ;
    PORT
      LAYER M4 ;
        RECT  0 29.04 0.084 29.064 ;
    END
  END b[82]
  PIN b[83]
    DIRECTION OUTPUT ;
    USE SIGNAL ;
    PORT
      LAYER M4 ;
        RECT  0 29.136 0.084 29.16 ;
    END
  END b[83]
  PIN b[84]
    DIRECTION OUTPUT ;
    USE SIGNAL ;
    PORT
      LAYER M4 ;
        RECT  0 29.232 0.084 29.256 ;
    END
  END b[84]
  PIN b[85]
    DIRECTION OUTPUT ;
    USE SIGNAL ;
    PORT
      LAYER M4 ;
        RECT  0 29.328 0.084 29.352 ;
    END
  END b[85]
  PIN b[86]
    DIRECTION OUTPUT ;
    USE SIGNAL ;
    PORT
      LAYER M4 ;
        RECT  0 29.424 0.084 29.448 ;
    END
  END b[86]
  PIN b[87]
    DIRECTION OUTPUT ;
    USE SIGNAL ;
    PORT
      LAYER M4 ;
        RECT  0 29.52 0.084 29.544 ;
    END
  END b[87]
  PIN b[88]
    DIRECTION OUTPUT ;
    USE SIGNAL ;
    PORT
      LAYER M4 ;
        RECT  0 29.616 0.084 29.64 ;
    END
  END b[88]
  PIN b[89]
    DIRECTION OUTPUT ;
    USE SIGNAL ;
    PORT
      LAYER M4 ;
        RECT  0 29.712 0.084 29.736 ;
    END
  END b[89]
  PIN b[8]
    DIRECTION OUTPUT ;
    USE SIGNAL ;
    PORT
      LAYER M4 ;
        RECT  0 15.024 0.084 15.048 ;
    END
  END b[8]
  PIN b[90]
    DIRECTION OUTPUT ;
    USE SIGNAL ;
    PORT
      LAYER M4 ;
        RECT  0 29.808 0.084 29.832 ;
    END
  END b[90]
  PIN b[91]
    DIRECTION OUTPUT ;
    USE SIGNAL ;
    PORT
      LAYER M4 ;
        RECT  0 29.904 0.084 29.928 ;
    END
  END b[91]
  PIN b[92]
    DIRECTION OUTPUT ;
    USE SIGNAL ;
    PORT
      LAYER M4 ;
        RECT  0 30 0.084 30.024 ;
    END
  END b[92]
  PIN b[93]
    DIRECTION OUTPUT ;
    USE SIGNAL ;
    PORT
      LAYER M4 ;
        RECT  0 30.096 0.084 30.12 ;
    END
  END b[93]
  PIN b[94]
    DIRECTION OUTPUT ;
    USE SIGNAL ;
    PORT
      LAYER M4 ;
        RECT  0 30.192 0.084 30.216 ;
    END
  END b[94]
  PIN b[95]
    DIRECTION OUTPUT ;
    USE SIGNAL ;
    PORT
      LAYER M4 ;
        RECT  0 30.288 0.084 30.312 ;
    END
  END b[95]
  PIN b[96]
    DIRECTION OUTPUT ;
    USE SIGNAL ;
    PORT
      LAYER M4 ;
        RECT  0 12.336 0.084 12.36 ;
    END
  END b[96]
  PIN b[97]
    DIRECTION OUTPUT ;
    USE SIGNAL ;
    PORT
      LAYER M4 ;
        RECT  0 12.432 0.084 12.456 ;
    END
  END b[97]
  PIN b[98]
    DIRECTION OUTPUT ;
    USE SIGNAL ;
    PORT
      LAYER M4 ;
        RECT  0 12.528 0.084 12.552 ;
    END
  END b[98]
  PIN b[99]
    DIRECTION OUTPUT ;
    USE SIGNAL ;
    PORT
      LAYER M4 ;
        RECT  0 12.624 0.084 12.648 ;
    END
  END b[99]
  PIN b[9]
    DIRECTION OUTPUT ;
    USE SIGNAL ;
    PORT
      LAYER M4 ;
        RECT  0 15.12 0.084 15.144 ;
    END
  END b[9]
  PIN ck
    DIRECTION INPUT ;
    USE SIGNAL ;
    PORT
      LAYER M3 ;
        RECT  21.996 46.403 22.014 46.44 ;
    END
  END ck
  PIN ck_s
    DIRECTION INPUT ;
    USE SIGNAL ;
    PORT
      LAYER M3 ;
        RECT  22.068 46.403 22.086 46.44 ;
    END
  END ck_s
  PIN en
    DIRECTION INPUT ;
    USE SIGNAL ;
    PORT
      LAYER M3 ;
        RECT  22.14 46.403 22.158 46.44 ;
    END
  END en
  PIN fault
    DIRECTION OUTPUT ;
    USE SIGNAL ;
    PORT
      LAYER M3 ;
        RECT  22.212 46.403 22.23 46.44 ;
    END
  END fault
  PIN k0
    DIRECTION INPUT ;
    USE SIGNAL ;
    PORT
      LAYER M3 ;
        RECT  22.284 46.403 22.302 46.44 ;
    END
  END k0
  PIN k1
    DIRECTION INPUT ;
    USE SIGNAL ;
    PORT
      LAYER M3 ;
        RECT  22.356 46.403 22.374 46.44 ;
    END
  END k1
  PIN k2
    DIRECTION INPUT ;
    USE SIGNAL ;
    PORT
      LAYER M3 ;
        RECT  22.428 46.403 22.446 46.44 ;
    END
  END k2
  PIN k3
    DIRECTION INPUT ;
    USE SIGNAL ;
    PORT
      LAYER M3 ;
        RECT  22.5 46.403 22.518 46.44 ;
    END
  END k3
  PIN rs
    DIRECTION INPUT ;
    USE SIGNAL ;
    PORT
      LAYER M3 ;
        RECT  22.572 46.403 22.59 46.44 ;
    END
  END rs
  PIN tie_hi
    DIRECTION OUTPUT ;
    USE SIGNAL ;
    PORT
      LAYER M3 ;
        RECT  22.644 46.403 22.662 46.44 ;
    END
  END tie_hi
  PIN tie_lo
    DIRECTION OUTPUT ;
    USE SIGNAL ;
    PORT
      LAYER M3 ;
        RECT  22.716 46.403 22.734 46.44 ;
    END
  END tie_lo
  PIN VSS
    DIRECTION INOUT ;
    USE GROUND ;
    PORT
      LAYER M5 ;
        RECT  42.9 2.137 43.02 44.303 ;
        RECT  40.2 2.137 40.32 44.303 ;
        RECT  37.5 2.137 37.62 44.303 ;
        RECT  34.8 2.137 34.92 44.303 ;
        RECT  32.1 2.137 32.22 44.303 ;
        RECT  29.4 2.137 29.52 44.303 ;
        RECT  26.7 2.137 26.82 44.303 ;
        RECT  24 2.137 24.12 44.303 ;
        RECT  21.3 2.137 21.42 44.303 ;
        RECT  18.6 2.137 18.72 44.303 ;
        RECT  15.9 2.137 16.02 44.303 ;
        RECT  13.2 2.137 13.32 44.303 ;
        RECT  10.5 2.137 10.62 44.303 ;
        RECT  7.8 2.137 7.92 44.303 ;
        RECT  5.1 2.137 5.22 44.303 ;
        RECT  2.4 2.137 2.52 44.303 ;
    END
  END VSS
  PIN VDD
    DIRECTION INOUT ;
    USE POWER ;
    PORT
      LAYER M5 ;
        RECT  43.092 2.151 43.212 44.289 ;
        RECT  40.392 2.151 40.512 44.289 ;
        RECT  37.692 2.151 37.812 44.289 ;
        RECT  34.992 2.151 35.112 44.289 ;
        RECT  32.292 2.151 32.412 44.289 ;
        RECT  29.592 2.151 29.712 44.289 ;
        RECT  26.892 2.151 27.012 44.289 ;
        RECT  24.192 2.151 24.312 44.289 ;
        RECT  21.492 2.151 21.612 44.289 ;
        RECT  18.792 2.151 18.912 44.289 ;
        RECT  16.092 2.151 16.212 44.289 ;
        RECT  13.392 2.151 13.512 44.289 ;
        RECT  10.692 2.151 10.812 44.289 ;
        RECT  7.992 2.151 8.112 44.289 ;
        RECT  5.292 2.151 5.412 44.289 ;
        RECT  2.592 2.151 2.712 44.289 ;
    END
  END VDD
  OBS
    LAYER RVTN ;
     RECT  2.16 2.16 44.28 2.295 ;
     RECT  2.16 2.565 44.28 2.835 ;
     RECT  2.16 3.105 44.28 3.375 ;
     RECT  2.16 3.645 44.28 3.915 ;
     RECT  2.16 4.185 44.28 4.455 ;
     RECT  2.16 4.725 44.28 4.995 ;
     RECT  2.16 5.265 44.28 5.535 ;
     RECT  2.16 5.805 44.28 6.075 ;
     RECT  2.16 6.345 44.28 6.615 ;
     RECT  2.16 6.885 44.28 7.155 ;
     RECT  2.16 7.425 44.28 7.695 ;
     RECT  2.16 7.965 44.28 8.235 ;
     RECT  2.16 8.505 44.28 8.775 ;
     RECT  2.16 9.045 44.28 9.315 ;
     RECT  2.16 9.585 44.28 9.855 ;
     RECT  2.16 10.125 44.28 10.395 ;
     RECT  2.16 10.665 44.28 10.935 ;
     RECT  2.16 11.205 44.28 11.475 ;
     RECT  2.16 11.745 44.28 12.015 ;
     RECT  2.16 12.285 44.28 12.555 ;
     RECT  2.16 12.825 44.28 13.095 ;
     RECT  2.16 13.365 44.28 13.635 ;
     RECT  2.16 13.905 44.28 14.175 ;
     RECT  2.16 14.445 44.28 14.715 ;
     RECT  2.16 14.985 44.28 15.255 ;
     RECT  2.16 15.525 44.28 15.795 ;
     RECT  2.16 16.065 44.28 16.335 ;
     RECT  2.16 16.605 44.28 16.875 ;
     RECT  2.16 17.145 44.28 17.415 ;
     RECT  2.16 17.685 44.28 17.955 ;
     RECT  2.16 18.225 44.28 18.495 ;
     RECT  2.16 18.765 44.28 19.035 ;
     RECT  2.16 19.305 44.28 19.575 ;
     RECT  2.16 19.845 44.28 20.115 ;
     RECT  2.16 20.385 44.28 20.655 ;
     RECT  2.16 20.925 44.28 21.195 ;
     RECT  2.16 21.465 44.28 21.735 ;
     RECT  2.16 22.005 44.28 22.275 ;
     RECT  2.16 22.545 44.28 22.815 ;
     RECT  2.16 23.085 44.28 23.355 ;
     RECT  2.16 23.625 44.28 23.895 ;
     RECT  2.16 24.165 44.28 24.435 ;
     RECT  2.16 24.705 44.28 24.975 ;
     RECT  2.16 25.245 44.28 25.515 ;
     RECT  2.16 25.785 44.28 26.055 ;
     RECT  2.16 26.325 44.28 26.595 ;
     RECT  2.16 26.865 44.28 27.135 ;
     RECT  2.16 27.405 44.28 27.675 ;
     RECT  2.16 27.945 44.28 28.215 ;
     RECT  2.16 28.485 44.28 28.755 ;
     RECT  2.16 29.025 44.28 29.295 ;
     RECT  2.16 29.565 44.28 29.835 ;
     RECT  2.16 30.105 44.28 30.375 ;
     RECT  2.16 30.645 44.28 30.915 ;
     RECT  2.16 31.185 44.28 31.455 ;
     RECT  2.16 31.725 44.28 31.995 ;
     RECT  2.16 32.265 44.28 32.535 ;
     RECT  2.16 32.805 44.28 33.075 ;
     RECT  2.16 33.345 44.28 33.615 ;
     RECT  2.16 33.885 44.28 34.155 ;
     RECT  2.16 34.425 44.28 34.695 ;
     RECT  2.16 34.965 44.28 35.235 ;
     RECT  2.16 35.505 44.28 35.775 ;
     RECT  2.16 36.045 44.28 36.315 ;
     RECT  2.16 36.585 44.28 36.855 ;
     RECT  2.16 37.125 44.28 37.395 ;
     RECT  2.16 37.665 44.28 37.935 ;
     RECT  2.16 38.205 44.28 38.475 ;
     RECT  2.16 38.745 44.28 39.015 ;
     RECT  2.16 39.285 44.28 39.555 ;
     RECT  2.16 39.825 44.28 40.095 ;
     RECT  2.16 40.365 44.28 40.635 ;
     RECT  2.16 40.905 44.28 41.175 ;
     RECT  2.16 41.445 44.28 41.715 ;
     RECT  2.16 41.985 44.28 42.255 ;
     RECT  2.16 42.525 44.28 42.795 ;
     RECT  2.16 43.065 44.28 43.335 ;
     RECT  2.16 43.605 44.28 43.875 ;
     RECT  2.16 44.145 44.28 44.28 ;
    LAYER RVTP ;
     RECT  2.16 2.295 44.28 2.565 ;
     RECT  2.16 2.835 44.28 3.105 ;
     RECT  2.16 3.375 44.28 3.645 ;
     RECT  2.16 3.915 44.28 4.185 ;
     RECT  2.16 4.455 44.28 4.725 ;
     RECT  2.16 4.995 44.28 5.265 ;
     RECT  2.16 5.535 44.28 5.805 ;
     RECT  2.16 6.075 44.28 6.345 ;
     RECT  2.16 6.615 44.28 6.885 ;
     RECT  2.16 7.155 44.28 7.425 ;
     RECT  2.16 7.695 44.28 7.965 ;
     RECT  2.16 8.235 44.28 8.505 ;
     RECT  2.16 8.775 44.28 9.045 ;
     RECT  2.16 9.315 44.28 9.585 ;
     RECT  2.16 9.855 44.28 10.125 ;
     RECT  2.16 10.395 44.28 10.665 ;
     RECT  2.16 10.935 44.28 11.205 ;
     RECT  2.16 11.475 44.28 11.745 ;
     RECT  2.16 12.015 44.28 12.285 ;
     RECT  2.16 12.555 44.28 12.825 ;
     RECT  2.16 13.095 44.28 13.365 ;
     RECT  2.16 13.635 44.28 13.905 ;
     RECT  2.16 14.175 44.28 14.445 ;
     RECT  2.16 14.715 44.28 14.985 ;
     RECT  2.16 15.255 44.28 15.525 ;
     RECT  2.16 15.795 44.28 16.065 ;
     RECT  2.16 16.335 44.28 16.605 ;
     RECT  2.16 16.875 44.28 17.145 ;
     RECT  2.16 17.415 44.28 17.685 ;
     RECT  2.16 17.955 44.28 18.225 ;
     RECT  2.16 18.495 44.28 18.765 ;
     RECT  2.16 19.035 44.28 19.305 ;
     RECT  2.16 19.575 44.28 19.845 ;
     RECT  2.16 20.115 44.28 20.385 ;
     RECT  2.16 20.655 44.28 20.925 ;
     RECT  2.16 21.195 44.28 21.465 ;
     RECT  2.16 21.735 44.28 22.005 ;
     RECT  2.16 22.275 44.28 22.545 ;
     RECT  2.16 22.815 44.28 23.085 ;
     RECT  2.16 23.355 44.28 23.625 ;
     RECT  2.16 23.895 44.28 24.165 ;
     RECT  2.16 24.435 44.28 24.705 ;
     RECT  2.16 24.975 44.28 25.245 ;
     RECT  2.16 25.515 44.28 25.785 ;
     RECT  2.16 26.055 44.28 26.325 ;
     RECT  2.16 26.595 44.28 26.865 ;
     RECT  2.16 27.135 44.28 27.405 ;
     RECT  2.16 27.675 44.28 27.945 ;
     RECT  2.16 28.215 44.28 28.485 ;
     RECT  2.16 28.755 44.28 29.025 ;
     RECT  2.16 29.295 44.28 29.565 ;
     RECT  2.16 29.835 44.28 30.105 ;
     RECT  2.16 30.375 44.28 30.645 ;
     RECT  2.16 30.915 44.28 31.185 ;
     RECT  2.16 31.455 44.28 31.725 ;
     RECT  2.16 31.995 44.28 32.265 ;
     RECT  2.16 32.535 44.28 32.805 ;
     RECT  2.16 33.075 44.28 33.345 ;
     RECT  2.16 33.615 44.28 33.885 ;
     RECT  2.16 34.155 44.28 34.425 ;
     RECT  2.16 34.695 44.28 34.965 ;
     RECT  2.16 35.235 44.28 35.505 ;
     RECT  2.16 35.775 44.28 36.045 ;
     RECT  2.16 36.315 44.28 36.585 ;
     RECT  2.16 36.855 44.28 37.125 ;
     RECT  2.16 37.395 44.28 37.665 ;
     RECT  2.16 37.935 44.28 38.205 ;
     RECT  2.16 38.475 44.28 38.745 ;
     RECT  2.16 39.015 44.28 39.285 ;
     RECT  2.16 39.555 44.28 39.825 ;
     RECT  2.16 40.095 44.28 40.365 ;
     RECT  2.16 40.635 44.28 40.905 ;
     RECT  2.16 41.175 44.28 41.445 ;
     RECT  2.16 41.715 44.28 41.985 ;
     RECT  2.16 42.255 44.28 42.525 ;
     RECT  2.16 42.795 44.28 43.065 ;
     RECT  2.16 43.335 44.28 43.605 ;
     RECT  2.16 43.875 44.28 44.145 ;
    LAYER M1 ;
     RECT  2.16 2.151 44.28 44.289 ;
    LAYER M2 ;
     RECT  0.103 15.03 0.203 15.048 ;
     RECT  0.103 27.306 0.463 27.324 ;
     RECT  0.463 12.294 0.499 12.852 ;
     RECT  0.103 13.95 0.499 13.968 ;
     RECT  0.463 27.306 0.499 27.666 ;
     RECT  0.499 11.826 0.535 13.086 ;
     RECT  0.499 13.95 0.535 14.238 ;
     RECT  0.499 27.306 0.535 27.774 ;
     RECT  0.175 29.106 0.535 29.124 ;
     RECT  0.535 11.826 1.175 14.742 ;
     RECT  1.175 11.826 2.16 14.544 ;
     RECT  0.535 15.804 2.16 16.524 ;
     RECT  0.535 23.868 2.16 24.426 ;
     RECT  0.535 27.144 2.16 27.936 ;
     RECT  0.535 28.998 2.16 29.124 ;
     RECT  1.975 30.078 2.16 30.096 ;
     RECT  2.16 2.151 8.419 44.289 ;
     RECT  8.419 2.106 14.171 44.289 ;
     RECT  22.207 45.621 22.603 45.639 ;
     RECT  22.351 46.386 22.603 46.404 ;
     RECT  22.603 45.621 22.883 46.404 ;
     RECT  22.883 46.386 22.919 46.404 ;
     RECT  22.883 45.621 23.567 45.639 ;
     RECT  14.171 2.151 37.975 44.289 ;
     RECT  37.975 2.151 39.263 44.334 ;
     RECT  39.263 2.151 44.28 44.289 ;
     RECT  44.28 6.318 44.735 6.408 ;
     RECT  44.28 15.84 44.771 15.858 ;
     RECT  44.28 7.668 44.807 7.956 ;
     RECT  44.28 19.386 44.843 20.484 ;
     RECT  44.28 21.276 44.987 24.192 ;
     RECT  44.987 23.328 45.023 24.192 ;
     RECT  44.28 30.618 45.059 33.066 ;
     RECT  45.023 23.598 45.167 24.192 ;
     RECT  44.807 7.776 45.311 7.956 ;
     RECT  44.28 9.936 45.635 13.464 ;
     RECT  44.843 20.196 45.635 20.484 ;
     RECT  44.987 21.276 45.635 22.23 ;
     RECT  45.059 30.888 45.635 33.066 ;
     RECT  45.635 20.196 45.671 20.214 ;
     RECT  45.635 21.276 45.671 21.294 ;
     RECT  44.28 25.056 45.671 25.074 ;
     RECT  45.635 31.734 45.671 33.066 ;
     RECT  45.671 32.31 45.707 33.066 ;
     RECT  45.635 9.936 45.743 12.888 ;
     RECT  45.167 24.174 45.743 24.192 ;
     RECT  45.743 11.826 45.779 12.312 ;
     RECT  44.28 8.856 45.995 9.108 ;
     RECT  45.743 9.936 46.031 11.034 ;
     RECT  45.995 8.856 46.067 8.874 ;
     RECT  44.843 19.386 46.103 19.404 ;
     RECT  45.311 7.776 46.139 7.794 ;
     RECT  45.635 22.131 46.147 22.23 ;
     RECT  44.28 16.92 46.175 17.514 ;
     RECT  46.147 22.131 46.175 22.806 ;
     RECT  45.779 12.096 46.211 12.312 ;
     RECT  44.735 6.318 46.247 6.336 ;
     RECT  46.175 17.496 46.247 17.514 ;
     RECT  46.211 12.096 46.283 12.114 ;
     RECT  45.707 33.048 46.355 33.066 ;
     RECT  46.031 10.44 46.391 11.034 ;
     RECT  46.175 22.788 46.391 22.806 ;
     RECT  46.391 11.016 46.427 11.034 ;
     RECT  46.327 24.606 46.427 24.624 ;
    LAYER M3 ;
     RECT  8.424 2.101 8.442 2.143 ;
     RECT  13.104 2.101 13.122 2.143 ;
     RECT  14.148 2.101 14.166 2.191 ;
     RECT  15.915 2.143 16.005 2.191 ;
     RECT  29.415 2.143 29.505 2.191 ;
     RECT  34.815 2.143 34.905 2.191 ;
     RECT  37.515 2.143 37.605 2.191 ;
     RECT  40.215 2.143 40.305 2.191 ;
     RECT  9.612 2.191 9.63 2.227 ;
     RECT  10.515 2.143 10.605 2.227 ;
     RECT  39.744 2.191 40.305 2.227 ;
     RECT  13.104 2.143 13.305 2.251 ;
     RECT  14.148 2.191 14.886 2.251 ;
     RECT  21.315 2.143 21.405 2.251 ;
     RECT  22.5 2.191 22.518 2.251 ;
     RECT  23.256 2.227 23.274 2.251 ;
     RECT  24.015 2.143 24.105 2.251 ;
     RECT  28.836 2.191 29.505 2.251 ;
     RECT  41.616 2.191 41.634 2.251 ;
     RECT  4.248 2.227 4.266 2.263 ;
     RECT  5.115 2.143 5.205 2.263 ;
     RECT  9.612 2.227 10.605 2.263 ;
     RECT  21.315 2.251 22.518 2.263 ;
     RECT  31.32 2.191 31.338 2.263 ;
     RECT  33.624 2.227 33.642 2.263 ;
     RECT  34.488 2.191 34.905 2.263 ;
     RECT  35.676 2.227 35.694 2.263 ;
     RECT  36.54 2.191 36.558 2.263 ;
     RECT  37.515 2.191 38.214 2.263 ;
     RECT  4.248 2.263 5.205 2.285 ;
     RECT  21.312 2.263 22.518 2.299 ;
     RECT  24.84 2.263 25.146 2.299 ;
     RECT  31.32 2.263 31.374 2.299 ;
     RECT  35.676 2.263 36.558 2.299 ;
     RECT  39.672 2.227 40.305 2.299 ;
     RECT  41.22 2.251 41.634 2.299 ;
     RECT  4.392 2.285 5.205 2.335 ;
     RECT  6.084 2.299 6.102 2.335 ;
     RECT  9.36 2.263 10.605 2.335 ;
     RECT  20.844 2.299 22.518 2.335 ;
     RECT  27.9 2.227 27.918 2.335 ;
     RECT  28.836 2.251 29.898 2.335 ;
     RECT  31.104 2.299 31.374 2.335 ;
     RECT  39.672 2.299 41.634 2.335 ;
     RECT  7.815 2.143 8.442 2.347 ;
     RECT  9.36 2.335 11.25 2.347 ;
     RECT  13.104 2.251 14.886 2.371 ;
     RECT  20.7 2.335 22.518 2.371 ;
     RECT  23.256 2.251 24.105 2.371 ;
     RECT  24.84 2.299 25.65 2.371 ;
     RECT  26.715 2.143 26.805 2.371 ;
     RECT  27.9 2.335 29.898 2.371 ;
     RECT  30.744 2.335 31.374 2.371 ;
     RECT  37.515 2.263 38.25 2.371 ;
     RECT  39.636 2.335 41.634 2.371 ;
     RECT  42.915 2.143 43.005 2.371 ;
     RECT  2.415 2.143 2.505 2.413 ;
     RECT  18.615 2.143 18.705 2.413 ;
     RECT  32.115 2.143 32.205 2.413 ;
     RECT  33.624 2.263 34.905 2.413 ;
     RECT  35.676 2.299 36.666 2.413 ;
     RECT  39.636 2.371 43.005 2.413 ;
     RECT  7.344 2.347 11.25 2.461 ;
     RECT  32.115 2.413 32.397 2.461 ;
     RECT  33.624 2.413 36.666 2.497 ;
     RECT  37.515 2.371 38.43 2.497 ;
     RECT  18.615 2.413 18.897 2.533 ;
     RECT  18.576 2.533 19.134 2.569 ;
     RECT  12.564 2.371 14.886 2.605 ;
     RECT  15.915 2.191 17.082 2.605 ;
     RECT  26.715 2.371 31.374 2.605 ;
     RECT  7.344 2.461 11.682 2.641 ;
     RECT  12.564 2.605 17.082 2.641 ;
     RECT  18.576 2.569 19.206 2.641 ;
     RECT  20.7 2.371 25.65 2.641 ;
     RECT  32.115 2.461 32.67 2.641 ;
     RECT  33.624 2.497 38.43 2.641 ;
     RECT  18.576 2.641 19.278 2.731 ;
     RECT  20.52 2.641 25.65 2.731 ;
     RECT  26.496 2.605 31.374 2.731 ;
     RECT  39.636 2.413 43.197 2.767 ;
     RECT  18.576 2.731 19.386 2.839 ;
     RECT  20.52 2.731 31.374 2.839 ;
     RECT  7.344 2.641 17.73 2.875 ;
     RECT  18.468 2.839 31.374 2.875 ;
     RECT  4.392 2.335 6.39 2.911 ;
     RECT  7.344 2.875 31.374 3.073 ;
     RECT  32.115 2.641 38.43 3.073 ;
     RECT  39.276 2.767 43.197 3.073 ;
     RECT  4.392 2.911 6.534 3.181 ;
     RECT  7.344 3.073 43.197 3.181 ;
     RECT  4.392 3.181 43.197 3.271 ;
     RECT  4.32 3.271 43.197 3.343 ;
     RECT  3.852 3.343 43.197 3.407 ;
     RECT  3.852 3.407 31.302 3.437 ;
     RECT  3.924 3.437 31.302 3.443 ;
     RECT  32.04 3.407 43.197 3.875 ;
     RECT  3.924 3.443 31.158 4.225 ;
     RECT  3.744 4.225 31.158 4.261 ;
     RECT  32.04 3.875 39.294 4.261 ;
     RECT  2.415 2.413 2.697 4.531 ;
     RECT  3.708 4.261 39.294 4.531 ;
     RECT  40.215 3.875 43.197 4.531 ;
     RECT  2.415 4.531 39.294 4.657 ;
     RECT  40.215 4.531 43.398 4.657 ;
     RECT  40.176 4.657 43.398 4.891 ;
     RECT  2.415 4.657 39.33 4.963 ;
     RECT  40.104 4.891 43.398 4.963 ;
     RECT  2.415 4.963 43.398 5.233 ;
     RECT  2.415 5.233 43.542 5.459 ;
     RECT  26.352 5.459 43.542 5.611 ;
     RECT  2.415 5.459 25.614 5.809 ;
     RECT  2.34 5.809 25.614 6.143 ;
     RECT  46.296 6.091 46.314 6.313 ;
     RECT  26.352 5.611 44.082 6.385 ;
     RECT  2.415 6.143 25.614 6.511 ;
     RECT  26.352 6.385 44.73 6.511 ;
     RECT  2.415 6.511 44.73 6.889 ;
     RECT  2.34 6.889 44.73 6.989 ;
     RECT  46.224 6.313 46.314 7.435 ;
     RECT  2.415 6.989 44.73 7.663 ;
     RECT  46.152 7.435 46.314 7.771 ;
     RECT  2.415 7.663 44.802 7.933 ;
     RECT  2.415 7.933 45.306 8.197 ;
     RECT  2.34 8.197 45.306 8.237 ;
     RECT  46.116 7.771 46.314 8.779 ;
     RECT  46.08 8.779 46.314 8.851 ;
     RECT  2.415 8.237 45.306 9.085 ;
     RECT  46.044 8.851 46.314 9.085 ;
     RECT  2.415 9.085 46.314 9.931 ;
     RECT  2.376 9.931 46.314 10.085 ;
     RECT  15.915 10.085 46.314 10.435 ;
     RECT  2.376 10.085 15.102 10.831 ;
     RECT  2.376 10.831 15.138 10.975 ;
     RECT  15.915 10.435 46.386 10.975 ;
     RECT  2.376 10.975 46.386 11.011 ;
     RECT  2.376 11.011 46.422 11.467 ;
     RECT  2.34 11.467 46.422 11.507 ;
     RECT  2.415 11.507 46.422 11.741 ;
     RECT  2.415 11.741 10.926 12.253 ;
     RECT  0.504 11.821 0.522 12.289 ;
     RECT  0.468 12.289 0.522 12.361 ;
     RECT  0.468 12.361 0.558 12.571 ;
     RECT  2.304 12.253 10.926 12.721 ;
     RECT  11.7 11.741 46.422 12.721 ;
     RECT  0.144 12.571 0.558 12.749 ;
     RECT  2.304 12.721 46.422 13.631 ;
     RECT  0.468 12.749 0.558 13.771 ;
     RECT  0.144 13.771 0.558 13.945 ;
     RECT  0.108 13.945 0.558 13.963 ;
     RECT  0.108 13.963 1.278 14.093 ;
     RECT  2.415 13.631 46.422 14.093 ;
     RECT  0.144 14.093 1.278 14.141 ;
     RECT  2.415 14.093 45.378 14.141 ;
     RECT  23.364 14.141 45.378 14.429 ;
     RECT  2.415 14.141 22.59 14.485 ;
     RECT  2.376 14.485 22.59 14.639 ;
     RECT  0.144 14.141 1.17 14.747 ;
     RECT  2.415 14.639 22.554 14.861 ;
     RECT  2.415 14.861 22.518 14.909 ;
     RECT  23.58 14.429 45.378 14.909 ;
     RECT  30.456 14.909 45.378 15.017 ;
     RECT  0.144 14.747 0.666 15.025 ;
     RECT  2.415 14.909 22.446 15.179 ;
     RECT  23.58 14.909 29.697 15.187 ;
     RECT  0.108 15.025 0.666 15.245 ;
     RECT  0.18 15.245 0.666 15.293 ;
     RECT  2.415 15.179 22.41 15.403 ;
     RECT  23.364 15.187 29.697 15.529 ;
     RECT  0.54 15.293 0.666 15.547 ;
     RECT  0.54 15.547 1.242 15.725 ;
     RECT  0.54 15.725 1.17 15.773 ;
     RECT  23.292 15.529 29.697 15.835 ;
     RECT  23.256 15.835 29.697 16.075 ;
     RECT  30.672 15.017 45.378 16.075 ;
     RECT  23.256 16.075 45.378 16.259 ;
     RECT  27.9 16.259 45.378 16.331 ;
     RECT  2.304 15.403 22.41 16.375 ;
     RECT  2.304 16.375 22.446 16.405 ;
     RECT  23.256 16.259 27.054 16.405 ;
     RECT  0.54 15.773 0.666 16.493 ;
     RECT  0.54 16.493 0.558 16.589 ;
     RECT  2.304 16.405 27.054 16.601 ;
     RECT  2.304 16.601 23.202 16.709 ;
     RECT  2.304 16.709 22.914 16.747 ;
     RECT  27.936 16.331 45.378 16.799 ;
     RECT  1.98 16.747 22.914 16.925 ;
     RECT  24.015 16.601 27.054 17.041 ;
     RECT  31.932 16.799 45.378 17.077 ;
     RECT  46.116 14.093 46.422 17.077 ;
     RECT  31.932 17.077 46.422 17.339 ;
     RECT  27.936 16.799 31.194 17.375 ;
     RECT  2.304 16.925 22.914 17.411 ;
     RECT  30.672 17.375 31.194 17.411 ;
     RECT  2.34 17.411 22.914 17.455 ;
     RECT  24.015 17.041 27.162 17.455 ;
     RECT  27.936 17.375 29.898 17.455 ;
     RECT  2.34 17.455 23.274 17.483 ;
     RECT  2.376 17.483 23.274 17.725 ;
     RECT  24.015 17.455 29.898 17.725 ;
     RECT  32.115 17.339 46.422 18.139 ;
     RECT  30.672 17.411 30.69 18.157 ;
     RECT  31.608 18.139 46.422 18.157 ;
     RECT  2.376 17.725 29.898 18.193 ;
     RECT  30.672 18.157 46.422 18.193 ;
     RECT  2.376 18.193 46.422 19.339 ;
     RECT  2.34 19.339 46.422 19.379 ;
     RECT  2.415 19.379 46.422 19.805 ;
     RECT  2.415 19.805 19.494 19.853 ;
     RECT  14.508 19.853 19.494 20.725 ;
     RECT  20.448 19.805 46.422 20.725 ;
     RECT  2.415 19.853 13.77 20.731 ;
     RECT  14.508 20.725 46.422 20.731 ;
     RECT  2.415 20.731 46.422 22.811 ;
     RECT  3.456 22.811 46.422 23.555 ;
     RECT  2.415 22.811 2.697 23.563 ;
     RECT  4.284 23.555 46.422 23.597 ;
     RECT  2.304 23.563 2.697 23.629 ;
     RECT  3.456 23.555 3.51 23.629 ;
     RECT  0.144 23.755 0.162 23.863 ;
     RECT  0.144 23.863 0.558 23.933 ;
     RECT  0.54 23.933 0.558 23.947 ;
     RECT  0.54 23.947 0.666 24.077 ;
     RECT  44.82 23.597 46.422 24.173 ;
     RECT  2.304 23.629 3.51 24.368 ;
     RECT  45.324 24.173 46.422 24.461 ;
     RECT  2.415 24.368 3.51 24.475 ;
     RECT  4.284 23.597 44.082 24.475 ;
     RECT  0.54 24.077 0.558 24.557 ;
     RECT  45.612 24.461 46.422 24.629 ;
     RECT  45.612 24.629 46.35 24.653 ;
     RECT  2.415 24.475 44.19 25.043 ;
     RECT  45.612 24.653 46.314 25.229 ;
     RECT  2.415 25.043 44.082 25.313 ;
     RECT  2.415 25.313 43.542 25.411 ;
     RECT  45.612 25.229 46.098 25.517 ;
     RECT  2.376 25.411 43.542 25.771 ;
     RECT  0.144 24.667 0.162 25.819 ;
     RECT  45.612 25.517 46.062 25.901 ;
     RECT  0.144 25.819 0.27 25.997 ;
     RECT  45.612 25.901 45.63 25.997 ;
     RECT  0.144 25.997 0.198 26.045 ;
     RECT  2.304 25.771 43.542 26.131 ;
     RECT  0.144 26.045 0.162 26.141 ;
     RECT  2.304 26.131 43.902 26.477 ;
     RECT  2.34 26.477 43.902 26.563 ;
     RECT  2.34 26.563 43.974 26.627 ;
     RECT  2.415 26.627 43.974 26.789 ;
     RECT  2.415 26.789 43.902 26.825 ;
     RECT  2.415 26.825 43.686 26.969 ;
     RECT  0.54 27.139 0.558 27.301 ;
     RECT  0.108 27.301 0.558 27.451 ;
     RECT  0.108 27.451 0.63 27.509 ;
     RECT  2.415 26.969 5.742 27.715 ;
     RECT  6.48 26.969 43.686 27.715 ;
     RECT  0.108 27.509 0.558 27.725 ;
     RECT  0.324 27.725 0.558 27.821 ;
     RECT  0.468 27.821 0.558 28.109 ;
     RECT  0.468 28.109 0.522 28.205 ;
     RECT  2.415 27.715 43.902 28.363 ;
     RECT  2.415 28.363 44.154 28.409 ;
     RECT  2.415 28.409 43.902 28.552 ;
     RECT  2.304 28.552 43.902 28.679 ;
     RECT  0.468 28.205 0.486 28.993 ;
     RECT  0.468 28.993 0.558 29.035 ;
     RECT  0.18 29.035 0.558 29.165 ;
     RECT  2.304 28.679 43.254 29.569 ;
     RECT  0.144 29.419 0.162 29.597 ;
     RECT  2.304 29.569 43.434 29.645 ;
     RECT  2.304 29.645 43.362 30.073 ;
     RECT  1.98 30.073 43.362 30.221 ;
     RECT  2.376 30.221 43.326 30.299 ;
     RECT  0.108 30.283 0.126 30.413 ;
     RECT  45.036 30.613 45.054 30.667 ;
     RECT  44.424 30.667 45.054 30.883 ;
     RECT  46.26 30.859 46.278 30.883 ;
     RECT  44.424 30.883 46.278 31.085 ;
     RECT  44.892 31.085 46.278 31.181 ;
     RECT  2.415 30.299 43.326 31.195 ;
     RECT  45 31.181 46.278 31.243 ;
     RECT  2.376 31.195 43.326 31.261 ;
     RECT  45 31.243 46.35 31.487 ;
     RECT  2.376 31.261 44.046 31.919 ;
     RECT  2.376 31.919 24.966 32.459 ;
     RECT  45.612 31.487 46.35 32.873 ;
     RECT  46.332 32.873 46.35 33.071 ;
     RECT  25.812 31.919 44.046 33.149 ;
     RECT  25.812 33.149 27.81 33.151 ;
     RECT  2.376 32.459 24.822 33.269 ;
     RECT  2.415 33.269 24.822 33.349 ;
     RECT  25.74 33.151 27.81 33.349 ;
     RECT  2.415 33.349 27.81 34.051 ;
     RECT  28.692 33.149 44.046 34.051 ;
     RECT  2.415 34.051 44.046 34.663 ;
     RECT  2.376 34.663 44.046 35.879 ;
     RECT  2.415 35.879 44.046 36.113 ;
     RECT  2.415 36.113 43.902 36.931 ;
     RECT  2.415 36.931 44.082 37.121 ;
     RECT  2.415 37.121 43.902 38.003 ;
     RECT  2.415 38.003 43.65 38.551 ;
     RECT  2.376 38.551 43.65 38.983 ;
     RECT  2.376 38.983 43.974 39.289 ;
     RECT  2.376 39.289 44.154 39.479 ;
     RECT  2.376 39.479 43.362 40.325 ;
     RECT  2.415 40.325 43.362 40.369 ;
     RECT  2.415 40.369 43.902 40.559 ;
     RECT  2.415 40.559 43.722 40.829 ;
     RECT  2.415 40.829 43.197 41.009 ;
     RECT  2.415 41.009 28.602 41.791 ;
     RECT  29.415 41.009 43.197 41.791 ;
     RECT  2.415 41.791 43.197 42.331 ;
     RECT  2.376 42.331 43.197 42.449 ;
     RECT  2.415 42.449 43.197 42.557 ;
     RECT  2.415 42.557 42.03 42.719 ;
     RECT  29.34 42.719 42.03 42.755 ;
     RECT  2.415 42.719 20.106 43.061 ;
     RECT  2.415 43.061 3.078 43.259 ;
     RECT  2.415 43.259 2.97 43.295 ;
     RECT  3.852 43.061 20.106 43.637 ;
     RECT  5.115 43.637 20.106 43.681 ;
     RECT  3.852 43.637 3.87 43.709 ;
     RECT  29.376 42.755 42.03 43.799 ;
     RECT  5.115 43.681 20.142 43.807 ;
     RECT  20.88 42.719 28.602 43.807 ;
     RECT  29.376 43.799 36.162 43.807 ;
     RECT  5.115 43.807 36.162 43.835 ;
     RECT  9.612 43.835 14.31 43.871 ;
     RECT  36.9 43.799 42.03 43.871 ;
     RECT  38.772 43.871 42.03 43.907 ;
     RECT  9.612 43.871 14.238 43.943 ;
     RECT  41.328 43.907 42.03 43.943 ;
     RECT  5.115 43.835 8.226 43.949 ;
     RECT  38.772 43.907 40.554 43.949 ;
     RECT  2.415 43.295 2.697 44.027 ;
     RECT  15.048 43.835 33.786 44.027 ;
     RECT  38.772 43.949 40.497 44.027 ;
     RECT  42.915 42.557 43.197 44.027 ;
     RECT  5.115 43.949 7.002 44.069 ;
     RECT  7.776 43.949 8.226 44.069 ;
     RECT  9.612 43.943 11.466 44.069 ;
     RECT  12.276 43.943 14.238 44.069 ;
     RECT  15.048 44.027 18.705 44.069 ;
     RECT  19.44 44.027 33.786 44.069 ;
     RECT  34.56 43.835 36.126 44.069 ;
     RECT  36.9 43.871 37.998 44.069 ;
     RECT  38.772 44.027 40.305 44.069 ;
     RECT  41.868 43.943 42.03 44.069 ;
     RECT  9.612 44.069 11.106 44.093 ;
     RECT  37.044 44.069 37.998 44.093 ;
     RECT  5.115 44.069 5.526 44.105 ;
     RECT  7.815 44.069 8.226 44.105 ;
     RECT  12.276 44.069 12.294 44.105 ;
     RECT  13.215 44.069 14.238 44.105 ;
     RECT  15.048 44.069 15.066 44.105 ;
     RECT  15.915 44.069 17.838 44.105 ;
     RECT  19.656 44.069 20.106 44.105 ;
     RECT  22.14 44.069 26.805 44.105 ;
     RECT  27.576 44.069 28.494 44.105 ;
     RECT  33.156 44.069 33.642 44.105 ;
     RECT  34.812 44.069 35.946 44.105 ;
     RECT  41.868 44.069 41.886 44.105 ;
     RECT  15.915 44.105 16.866 44.141 ;
     RECT  20.952 44.069 21.405 44.141 ;
     RECT  27.972 44.105 27.99 44.141 ;
     RECT  30.96 44.069 31.014 44.141 ;
     RECT  33.156 44.105 33.174 44.141 ;
     RECT  10.296 44.093 11.106 44.147 ;
     RECT  7.815 44.105 8.19 44.177 ;
     RECT  13.215 44.105 14.058 44.177 ;
     RECT  22.14 44.105 24.426 44.177 ;
     RECT  34.815 44.105 35.19 44.177 ;
     RECT  29.415 44.069 30.222 44.213 ;
     RECT  30.996 44.141 31.014 44.213 ;
     RECT  38.772 44.069 39.258 44.213 ;
     RECT  10.515 44.147 11.106 44.249 ;
     RECT  13.215 44.177 13.77 44.249 ;
     RECT  15.915 44.141 16.578 44.249 ;
     RECT  17.676 44.105 17.694 44.249 ;
     RECT  19.656 44.105 19.674 44.249 ;
     RECT  25.2 44.105 25.218 44.249 ;
     RECT  26.064 44.105 26.805 44.249 ;
     RECT  2.415 44.027 2.505 44.297 ;
     RECT  5.115 44.105 5.205 44.297 ;
     RECT  7.815 44.177 7.905 44.297 ;
     RECT  10.515 44.249 10.605 44.297 ;
     RECT  13.215 44.249 13.305 44.297 ;
     RECT  15.915 44.249 16.005 44.297 ;
     RECT  18.615 44.069 18.705 44.297 ;
     RECT  21.315 44.141 21.405 44.297 ;
     RECT  22.14 44.177 24.105 44.297 ;
     RECT  26.715 44.249 26.805 44.297 ;
     RECT  29.415 44.213 29.505 44.297 ;
     RECT  32.115 44.069 32.205 44.297 ;
     RECT  34.815 44.177 34.905 44.297 ;
     RECT  37.515 44.093 37.998 44.297 ;
     RECT  40.215 44.069 40.305 44.297 ;
     RECT  42.915 44.027 43.005 44.297 ;
     RECT  37.98 44.297 37.998 44.339 ;
     RECT  38.808 44.213 39.258 44.339 ;
     RECT  22.14 44.297 23.562 45.644 ;
     RECT  22.14 45.644 22.914 46.171 ;
     RECT  22.068 46.171 22.914 46.267 ;
     RECT  21.672 46.267 22.914 46.397 ;
     RECT  21.996 46.397 22.914 46.409 ;
     RECT  21.996 46.409 22.734 46.428 ;
    LAYER M4 ;
     RECT  0.06 23.472 0.097 30.312 ;
     RECT  0.06 12.336 0.533 17.256 ;
     RECT  0.533 12.432 2.329 17.256 ;
     RECT  0.097 23.472 2.365 30.408 ;
     RECT  2.329 8.208 2.408 8.232 ;
     RECT  2.329 11.472 2.408 17.256 ;
     RECT  2.329 19.344 2.408 19.368 ;
     RECT  2.365 23.472 2.408 31.224 ;
     RECT  2.365 38.784 2.408 39.24 ;
     RECT  2.408 2.148 2.512 44.292 ;
     RECT  2.512 2.418 2.704 44.022 ;
     RECT  2.704 18.144 2.819 19.512 ;
     RECT  2.704 38.208 2.837 40.632 ;
     RECT  2.704 11.136 2.867 11.496 ;
     RECT  2.704 36.096 2.873 36.984 ;
     RECT  2.819 18.144 3.107 19.368 ;
     RECT  2.704 20.544 3.197 26.424 ;
     RECT  2.704 33.552 3.233 34.92 ;
     RECT  2.704 27.456 3.443 31.56 ;
     RECT  3.197 20.64 3.485 26.424 ;
     RECT  3.485 21.648 3.491 26.424 ;
     RECT  2.704 8.208 3.665 10.056 ;
     RECT  2.704 5.856 3.697 6.12 ;
     RECT  2.704 12.48 3.733 16.968 ;
     RECT  3.107 18.144 3.733 18.264 ;
     RECT  2.837 38.208 3.769 39.24 ;
     RECT  2.704 4.848 3.827 4.872 ;
     RECT  3.233 33.552 3.841 34.68 ;
     RECT  3.781 3.408 3.881 3.432 ;
     RECT  3.491 23.52 3.925 26.424 ;
     RECT  3.443 27.456 3.925 31.224 ;
     RECT  2.837 40.608 3.973 40.632 ;
     RECT  2.704 41.616 4.021 41.88 ;
     RECT  3.913 43.296 4.021 43.32 ;
     RECT  3.841 32.976 4.093 34.68 ;
     RECT  2.873 36.096 4.093 36.504 ;
     RECT  3.769 37.92 4.129 39.24 ;
     RECT  3.973 40.464 4.129 40.632 ;
     RECT  4.093 36.048 4.165 36.504 ;
     RECT  2.867 11.136 4.201 11.4 ;
     RECT  4.201 11.088 4.273 11.4 ;
     RECT  3.733 12.48 4.273 18.264 ;
     RECT  3.107 19.296 4.273 19.32 ;
     RECT  4.165 36.048 4.273 36.6 ;
     RECT  4.129 37.584 4.273 40.632 ;
     RECT  4.273 11.088 4.309 18.264 ;
     RECT  4.273 19.296 4.309 19.416 ;
     RECT  4.093 32.592 4.309 34.68 ;
     RECT  3.697 5.856 4.417 6.84 ;
     RECT  4.021 41.616 4.417 43.32 ;
     RECT  4.417 5.856 4.453 6.888 ;
     RECT  4.309 32.544 4.453 34.68 ;
     RECT  4.273 35.808 4.453 40.632 ;
     RECT  4.453 32.544 4.501 40.632 ;
     RECT  4.417 41.616 4.501 43.56 ;
     RECT  3.485 20.64 4.597 20.664 ;
     RECT  3.491 21.648 4.597 21.672 ;
     RECT  4.309 11.088 4.669 19.416 ;
     RECT  4.597 20.64 4.669 21.672 ;
     RECT  4.453 5.568 4.741 6.888 ;
     RECT  3.925 23.52 4.741 31.224 ;
     RECT  3.665 8.736 4.813 10.056 ;
     RECT  4.669 11.088 4.813 21.672 ;
     RECT  4.741 22.8 4.813 31.224 ;
     RECT  4.237 2.256 4.885 2.28 ;
     RECT  3.913 3.696 4.885 3.72 ;
     RECT  4.885 2.256 5.065 3.72 ;
     RECT  5.065 2.256 5.108 3.96 ;
     RECT  4.741 5.568 5.108 7.128 ;
     RECT  4.813 8.736 5.108 21.672 ;
     RECT  4.813 22.8 5.108 31.512 ;
     RECT  4.501 32.544 5.108 43.56 ;
     RECT  5.108 2.148 5.212 44.292 ;
     RECT  5.212 2.418 5.404 44.022 ;
     RECT  5.404 5.568 5.555 21.144 ;
     RECT  5.404 22.752 5.573 43.992 ;
     RECT  5.555 5.568 5.581 21 ;
     RECT  5.404 2.736 5.609 3.96 ;
     RECT  5.573 22.752 5.753 31.416 ;
     RECT  5.581 5.568 6.005 19.56 ;
     RECT  5.753 22.752 6.293 26.808 ;
     RECT  5.753 27.984 6.613 31.416 ;
     RECT  5.573 32.496 6.613 43.992 ;
     RECT  6.005 5.568 6.829 6.888 ;
     RECT  6.829 5.088 6.901 6.888 ;
     RECT  5.581 20.544 7.093 21 ;
     RECT  6.901 4.512 7.189 6.888 ;
     RECT  6.005 8.256 7.189 19.56 ;
     RECT  5.609 2.736 7.333 3.432 ;
     RECT  7.093 20.544 7.333 21.144 ;
     RECT  6.293 22.752 7.441 22.776 ;
     RECT  7.189 4.512 7.657 19.56 ;
     RECT  7.333 20.544 7.657 21.528 ;
     RECT  7.333 2.352 7.765 3.432 ;
     RECT  7.657 4.512 7.765 21.528 ;
     RECT  7.765 2.352 7.808 21.528 ;
     RECT  7.441 22.512 7.808 22.776 ;
     RECT  6.293 23.904 7.808 26.808 ;
     RECT  6.613 27.984 7.808 43.992 ;
     RECT  7.808 2.148 7.912 44.292 ;
     RECT  7.912 2.352 8.104 44.022 ;
     RECT  8.104 5.376 8.237 27.384 ;
     RECT  8.104 28.8 8.243 42.744 ;
     RECT  8.243 28.8 8.309 33.384 ;
     RECT  8.237 5.76 8.813 27.384 ;
     RECT  8.813 5.76 8.921 16.92 ;
     RECT  8.104 4.224 9.097 4.248 ;
     RECT  8.921 5.76 9.101 9.096 ;
     RECT  8.243 34.56 9.107 42.744 ;
     RECT  9.097 4.224 9.137 4.584 ;
     RECT  9.107 34.608 9.155 42.744 ;
     RECT  9.155 42.24 9.169 42.744 ;
     RECT  9.137 4.56 9.205 4.584 ;
     RECT  9.101 5.76 9.205 8.424 ;
     RECT  8.309 28.8 9.245 33.096 ;
     RECT  8.104 2.352 9.353 2.616 ;
     RECT  9.205 4.56 9.353 8.424 ;
     RECT  9.353 2.352 9.389 2.376 ;
     RECT  9.169 42.24 9.601 43.272 ;
     RECT  9.245 32.784 9.637 33.096 ;
     RECT  8.813 18.096 9.709 27.384 ;
     RECT  8.921 10.08 9.889 16.92 ;
     RECT  9.709 18.096 9.997 27.432 ;
     RECT  9.997 18.096 10.076 27.624 ;
     RECT  9.155 34.608 10.177 40.68 ;
     RECT  9.601 42.24 10.177 44.088 ;
     RECT  9.245 28.8 10.213 31.8 ;
     RECT  9.637 32.784 10.213 33.288 ;
     RECT  10.213 28.8 10.249 33.288 ;
     RECT  10.177 34.608 10.249 44.088 ;
     RECT  10.249 28.8 10.261 44.088 ;
     RECT  9.353 5.088 10.501 8.424 ;
     RECT  9.889 9.504 10.501 16.92 ;
     RECT  10.501 5.088 10.508 16.92 ;
     RECT  10.076 18.096 10.508 27.816 ;
     RECT  10.261 28.8 10.508 44.136 ;
     RECT  10.508 2.148 10.612 44.292 ;
     RECT  10.612 2.418 10.804 44.088 ;
     RECT  10.804 18.72 10.865 27.384 ;
     RECT  10.804 2.832 10.973 17.448 ;
     RECT  10.804 28.512 11.075 44.088 ;
     RECT  10.973 2.832 11.405 8.184 ;
     RECT  10.865 18.72 11.459 26.376 ;
     RECT  11.459 18.912 11.477 26.376 ;
     RECT  11.405 4.512 11.513 8.184 ;
     RECT  11.075 34.08 11.657 44.088 ;
     RECT  11.513 4.512 11.699 7.992 ;
     RECT  10.973 9.504 12.013 17.448 ;
     RECT  12.013 9.36 12.085 17.448 ;
     RECT  11.477 18.96 12.157 26.376 ;
     RECT  10.865 27.36 12.157 27.384 ;
     RECT  12.157 18.96 12.161 27.384 ;
     RECT  11.699 5.04 12.481 7.992 ;
     RECT  12.481 5.04 12.661 8.04 ;
     RECT  12.085 9.36 12.661 17.64 ;
     RECT  11.075 28.512 12.697 33.096 ;
     RECT  12.661 5.04 12.733 17.64 ;
     RECT  12.733 5.04 12.769 17.688 ;
     RECT  12.161 18.96 12.769 27.192 ;
     RECT  12.697 28.512 12.805 33.384 ;
     RECT  11.657 34.416 12.805 44.088 ;
     RECT  11.405 2.832 12.841 2.856 ;
     RECT  12.841 2.832 13.208 3.288 ;
     RECT  12.769 4.512 13.208 27.192 ;
     RECT  12.805 28.512 13.208 44.088 ;
     RECT  13.208 2.148 13.312 44.292 ;
     RECT  13.312 2.256 13.504 44.022 ;
     RECT  13.504 2.256 13.619 3.048 ;
     RECT  13.504 4.512 13.781 31.992 ;
     RECT  13.781 4.512 13.997 21.528 ;
     RECT  13.997 9.36 14.033 21.528 ;
     RECT  13.781 22.56 14.044 31.992 ;
     RECT  13.504 32.976 14.069 43.848 ;
     RECT  14.033 9.456 14.213 14.136 ;
     RECT  14.044 22.56 14.213 27.48 ;
     RECT  14.213 22.848 14.249 27.48 ;
     RECT  14.033 15.312 14.321 21.528 ;
     RECT  13.997 4.512 14.749 7.944 ;
     RECT  13.619 3.024 14.821 3.048 ;
     RECT  14.069 32.976 14.825 37.128 ;
     RECT  14.044 28.848 14.857 31.992 ;
     RECT  14.749 4.176 14.861 7.944 ;
     RECT  14.213 9.504 14.897 14.136 ;
     RECT  14.321 15.504 14.915 21.528 ;
     RECT  14.069 38.208 15.037 43.848 ;
     RECT  14.857 28.848 15.145 32.664 ;
     RECT  14.897 11.136 15.361 14.136 ;
     RECT  14.821 2.88 15.397 3.096 ;
     RECT  15.361 11.136 15.397 14.184 ;
     RECT  14.915 15.504 15.397 18.264 ;
     RECT  14.861 4.416 15.541 7.944 ;
     RECT  15.541 4.416 15.781 8.472 ;
     RECT  14.897 9.504 15.781 10.152 ;
     RECT  15.397 2.88 15.908 3.336 ;
     RECT  15.781 4.416 15.908 10.152 ;
     RECT  15.397 11.136 15.908 18.264 ;
     RECT  14.915 19.296 15.908 21.528 ;
     RECT  14.249 22.848 15.908 27.336 ;
     RECT  15.145 28.464 15.908 32.664 ;
     RECT  14.825 34.416 15.908 37.128 ;
     RECT  15.037 38.208 15.908 43.944 ;
     RECT  15.908 2.148 16.012 44.292 ;
     RECT  16.012 2.256 16.204 44.022 ;
     RECT  16.204 41.376 16.229 42.744 ;
     RECT  16.204 22.56 16.265 40.152 ;
     RECT  16.204 2.256 16.355 2.28 ;
     RECT  16.265 22.56 16.409 39.912 ;
     RECT  16.204 3.936 16.625 21.528 ;
     RECT  16.409 22.56 16.841 37.08 ;
     RECT  16.625 9.6 16.877 21.528 ;
     RECT  16.841 22.56 16.985 37.032 ;
     RECT  16.625 3.936 17.201 8.52 ;
     RECT  16.409 38.112 17.237 39.912 ;
     RECT  16.229 41.712 17.237 42.744 ;
     RECT  16.877 9.6 17.309 17.64 ;
     RECT  17.201 3.936 17.417 6.024 ;
     RECT  17.417 3.936 17.453 4.68 ;
     RECT  17.237 38.112 17.459 39.288 ;
     RECT  16.877 18.768 17.557 21.528 ;
     RECT  16.985 22.56 17.557 36.888 ;
     RECT  17.309 9.888 18.133 17.64 ;
     RECT  17.557 18.768 18.133 36.888 ;
     RECT  17.485 3.36 18.493 3.384 ;
     RECT  18.493 3.312 18.608 3.384 ;
     RECT  17.453 4.416 18.608 4.68 ;
     RECT  17.417 5.808 18.608 6.024 ;
     RECT  17.201 7.344 18.608 8.52 ;
     RECT  18.133 9.888 18.608 36.888 ;
     RECT  17.459 38.496 18.608 39.288 ;
     RECT  17.953 41.232 18.608 41.256 ;
     RECT  17.237 42.72 18.608 42.744 ;
     RECT  16.204 43.824 18.608 43.848 ;
     RECT  18.608 2.148 18.712 44.292 ;
     RECT  18.712 2.418 18.904 44.022 ;
     RECT  18.904 3.312 19.001 3.432 ;
     RECT  18.904 4.56 19.037 14.184 ;
     RECT  18.904 19.776 19.043 26.616 ;
     RECT  19.001 3.36 19.073 3.432 ;
     RECT  18.904 15.312 19.081 18.792 ;
     RECT  18.904 27.648 19.109 31.848 ;
     RECT  19.081 15.312 19.217 17.64 ;
     RECT  19.043 19.92 19.379 26.616 ;
     RECT  18.904 42.72 19.433 43.56 ;
     RECT  19.037 4.56 19.469 14.136 ;
     RECT  19.469 4.56 19.505 12.888 ;
     RECT  18.904 32.88 19.523 36.888 ;
     RECT  18.904 38.16 19.901 38.76 ;
     RECT  19.379 22.752 19.933 26.616 ;
     RECT  19.109 27.648 19.933 31.8 ;
     RECT  18.904 40.992 20.06 41.256 ;
     RECT  19.433 42.72 20.06 42.84 ;
     RECT  19.933 22.752 20.077 31.8 ;
     RECT  19.523 32.88 20.077 36.456 ;
     RECT  20.06 40.992 20.101 42.84 ;
     RECT  19.081 18.768 20.113 18.792 ;
     RECT  19.379 19.92 20.113 21.624 ;
     RECT  19.505 4.56 20.117 4.584 ;
     RECT  20.101 40.56 20.147 42.84 ;
     RECT  20.147 42.816 20.161 42.84 ;
     RECT  19.505 5.568 20.437 12.888 ;
     RECT  19.469 13.92 20.437 14.136 ;
     RECT  20.437 5.568 20.689 14.136 ;
     RECT  19.073 3.408 20.797 3.432 ;
     RECT  20.797 2.736 20.833 3.432 ;
     RECT  20.113 18.768 21.013 21.624 ;
     RECT  20.077 22.752 21.013 36.456 ;
     RECT  21.013 18.72 21.049 21.624 ;
     RECT  21.013 22.656 21.049 36.456 ;
     RECT  19.901 38.16 21.049 38.52 ;
     RECT  20.147 40.56 21.049 41.256 ;
     RECT  20.689 4.656 21.085 14.136 ;
     RECT  21.049 37.584 21.157 38.52 ;
     RECT  21.049 39.6 21.193 41.256 ;
     RECT  21.157 42.768 21.193 42.792 ;
     RECT  19.217 15.312 21.265 17.448 ;
     RECT  20.833 2.544 21.308 3.432 ;
     RECT  21.085 4.656 21.308 14.328 ;
     RECT  21.265 15.312 21.308 17.496 ;
     RECT  21.049 18.72 21.308 36.456 ;
     RECT  21.157 37.44 21.308 38.52 ;
     RECT  21.193 39.6 21.308 42.792 ;
     RECT  21.308 2.148 21.412 44.292 ;
     RECT  21.412 2.256 21.604 44.022 ;
     RECT  16.885 46.368 21.661 46.392 ;
     RECT  21.604 5.232 21.665 6.312 ;
     RECT  21.604 37.584 21.701 38.52 ;
     RECT  21.661 46.272 21.701 46.392 ;
     RECT  21.604 2.256 21.731 4.104 ;
     RECT  21.604 39.6 21.731 42.744 ;
     RECT  21.701 37.584 21.845 38.184 ;
     RECT  21.604 17.04 21.881 35.832 ;
     RECT  21.881 17.04 21.989 27.96 ;
     RECT  21.701 46.272 22.025 46.296 ;
     RECT  21.845 37.968 22.097 38.184 ;
     RECT  22.028 46.176 22.115 46.2 ;
     RECT  21.731 2.256 22.133 2.808 ;
     RECT  21.989 22.752 22.277 27.96 ;
     RECT  21.731 4.08 22.313 4.104 ;
     RECT  21.881 28.992 22.348 35.832 ;
     RECT  21.989 17.04 22.385 21.72 ;
     RECT  21.604 7.392 22.421 16.056 ;
     RECT  22.277 23.28 22.421 27.96 ;
     RECT  22.385 17.472 22.529 21.72 ;
     RECT  22.133 2.544 22.637 2.808 ;
     RECT  21.731 39.6 22.745 42.456 ;
     RECT  22.745 40.08 22.777 42.456 ;
     RECT  22.421 23.328 22.817 27.96 ;
     RECT  22.777 40.08 22.817 43.032 ;
     RECT  22.421 9.792 22.837 16.056 ;
     RECT  21.665 5.232 22.885 6.12 ;
     RECT  22.348 34.896 22.885 35.832 ;
     RECT  22.817 40.32 22.885 43.032 ;
     RECT  22.421 7.392 22.889 8.808 ;
     RECT  22.885 40.32 22.931 43.32 ;
     RECT  22.348 28.992 22.961 33.912 ;
     RECT  22.637 2.544 23.245 2.616 ;
     RECT  22.837 9.792 23.605 16.44 ;
     RECT  22.529 17.472 23.605 21.24 ;
     RECT  23.245 2.256 23.641 2.616 ;
     RECT  23.353 3.696 23.641 3.72 ;
     RECT  22.097 37.968 23.701 38.088 ;
     RECT  22.889 7.44 23.965 8.808 ;
     RECT  22.817 23.328 23.965 27.624 ;
     RECT  23.641 2.256 24.008 3.72 ;
     RECT  22.885 5.184 24.008 6.12 ;
     RECT  23.965 7.344 24.008 8.808 ;
     RECT  23.605 9.792 24.008 21.24 ;
     RECT  23.965 23.328 24.008 28.2 ;
     RECT  22.961 29.184 24.008 33.912 ;
     RECT  22.885 34.896 24.008 36.024 ;
     RECT  23.701 37.344 24.008 38.088 ;
     RECT  23.353 39.072 24.008 39.096 ;
     RECT  22.931 40.32 24.008 41.928 ;
     RECT  22.931 43.008 24.008 43.32 ;
     RECT  24.008 2.148 24.112 44.292 ;
     RECT  24.112 2.418 24.304 44.022 ;
     RECT  24.304 25.248 24.437 28.2 ;
     RECT  24.304 10.08 24.481 23.88 ;
     RECT  24.304 36.48 24.508 43.32 ;
     RECT  24.304 33.552 24.515 35.304 ;
     RECT  24.508 41.616 24.517 43.32 ;
     RECT  24.304 29.232 24.545 32.04 ;
     RECT  24.517 41.904 24.581 43.32 ;
     RECT  24.545 29.232 24.689 31.944 ;
     RECT  24.437 25.248 24.797 26.664 ;
     RECT  24.581 41.952 24.869 43.32 ;
     RECT  24.508 36.48 25.121 40.44 ;
     RECT  24.515 35.28 25.265 35.304 ;
     RECT  25.121 36.48 25.445 39.48 ;
     RECT  24.515 33.552 25.477 34.104 ;
     RECT  24.869 42.768 25.477 43.32 ;
     RECT  25.477 42.768 25.517 44.088 ;
     RECT  25.517 43.008 25.523 44.088 ;
     RECT  25.523 43.296 25.564 44.088 ;
     RECT  24.481 10.08 25.657 17.832 ;
     RECT  25.445 36.48 25.715 39.336 ;
     RECT  24.304 3.12 25.765 9.048 ;
     RECT  25.477 33.552 25.837 34.2 ;
     RECT  24.797 25.248 26.017 26.376 ;
     RECT  24.437 28.176 26.017 28.2 ;
     RECT  24.689 29.232 26.017 31.512 ;
     RECT  25.837 33.024 26.017 34.2 ;
     RECT  26.017 32.88 26.089 34.2 ;
     RECT  25.657 10.032 26.108 17.832 ;
     RECT  24.481 18.816 26.108 23.88 ;
     RECT  26.089 32.496 26.108 34.2 ;
     RECT  25.765 2.832 26.197 9.048 ;
     RECT  26.108 10.032 26.197 23.88 ;
     RECT  26.197 2.832 26.341 23.88 ;
     RECT  26.108 32.496 26.341 34.872 ;
     RECT  25.715 36.48 26.341 39.288 ;
     RECT  26.017 28.176 26.449 31.512 ;
     RECT  26.341 32.496 26.449 39.288 ;
     RECT  26.341 2.832 26.485 23.976 ;
     RECT  26.017 24.96 26.485 26.376 ;
     RECT  26.485 2.832 26.581 26.376 ;
     RECT  26.581 2.544 26.708 26.376 ;
     RECT  26.449 28.176 26.708 39.288 ;
     RECT  26.161 40.32 26.708 40.344 ;
     RECT  25.628 41.664 26.708 41.688 ;
     RECT  25.564 43.296 26.708 43.656 ;
     RECT  26.708 2.148 26.812 44.292 ;
     RECT  26.812 2.418 27.004 44.022 ;
     RECT  27.004 35.808 27.173 39.288 ;
     RECT  27.004 3.696 27.281 17.496 ;
     RECT  27.173 36.672 27.353 39.288 ;
     RECT  27.004 28.416 27.425 34.2 ;
     RECT  27.425 28.512 27.461 34.2 ;
     RECT  27.281 3.696 27.587 16.92 ;
     RECT  27.004 42.672 27.605 43.944 ;
     RECT  27.004 40.32 27.641 41.688 ;
     RECT  27.605 42.672 27.677 43.656 ;
     RECT  27.677 42.672 27.893 43.32 ;
     RECT  27.641 41.664 27.929 41.688 ;
     RECT  27.587 3.696 27.971 11.496 ;
     RECT  27.461 28.512 28.037 33.912 ;
     RECT  28.021 18.192 28.108 18.216 ;
     RECT  28.037 31.92 28.181 33.912 ;
     RECT  27.971 4.848 28.307 9.624 ;
     RECT  27.004 19.776 28.397 27.384 ;
     RECT  27.587 12.528 28.429 16.92 ;
     RECT  27.353 37.056 28.429 39.288 ;
     RECT  28.429 12.528 28.465 16.968 ;
     RECT  27.971 10.608 28.573 11.496 ;
     RECT  28.465 12.528 28.573 17.064 ;
     RECT  28.037 28.512 28.645 30.648 ;
     RECT  27.641 40.32 28.741 40.344 ;
     RECT  28.429 37.056 28.837 39.336 ;
     RECT  28.741 40.32 28.837 40.824 ;
     RECT  28.837 37.056 28.885 40.824 ;
     RECT  28.397 19.824 29.005 27.384 ;
     RECT  28.645 28.416 29.005 30.648 ;
     RECT  28.573 10.608 29.029 17.064 ;
     RECT  28.181 31.92 29.077 32.04 ;
     RECT  28.181 33.072 29.077 33.912 ;
     RECT  28.933 35.184 29.077 35.208 ;
     RECT  28.307 4.992 29.149 9.624 ;
     RECT  29.029 10.608 29.149 17.112 ;
     RECT  29.005 19.824 29.249 30.648 ;
     RECT  29.077 33.072 29.257 35.208 ;
     RECT  28.465 42.192 29.269 42.216 ;
     RECT  27.893 43.296 29.269 43.32 ;
     RECT  29.249 19.824 29.329 30.744 ;
     RECT  29.077 31.776 29.329 32.04 ;
     RECT  27.004 2.544 29.408 2.568 ;
     RECT  29.149 4.992 29.408 17.112 ;
     RECT  29.077 18.144 29.408 18.168 ;
     RECT  29.329 19.824 29.408 32.04 ;
     RECT  29.257 33.072 29.408 35.256 ;
     RECT  28.885 36.288 29.408 40.824 ;
     RECT  29.269 42.192 29.408 43.32 ;
     RECT  29.408 2.148 29.512 44.292 ;
     RECT  29.512 2.256 29.704 44.022 ;
     RECT  29.704 6.048 29.891 16.92 ;
     RECT  29.704 2.256 29.932 2.28 ;
     RECT  29.704 42.096 30.189 43.32 ;
     RECT  29.891 6.048 30.377 10.392 ;
     RECT  29.704 35.184 30.377 35.4 ;
     RECT  30.377 6.048 30.449 9.144 ;
     RECT  30.377 10.32 30.521 10.392 ;
     RECT  29.704 37.392 30.521 38.808 ;
     RECT  30.377 35.184 30.629 35.256 ;
     RECT  30.521 37.392 30.733 38.184 ;
     RECT  30.189 42.096 30.769 42.744 ;
     RECT  30.521 10.368 30.809 10.392 ;
     RECT  30.629 35.184 30.809 35.208 ;
     RECT  29.891 11.424 30.881 16.92 ;
     RECT  30.449 6.048 30.913 7.8 ;
     RECT  30.881 11.424 31.1 14.232 ;
     RECT  30.881 15.408 31.165 16.92 ;
     RECT  30.913 5.136 31.429 7.8 ;
     RECT  30.449 8.784 31.429 9.144 ;
     RECT  31.429 5.136 31.477 9.144 ;
     RECT  30.769 42 31.633 42.744 ;
     RECT  30.733 37.296 31.697 38.184 ;
     RECT  29.704 19.824 31.777 33.576 ;
     RECT  31.477 5.136 31.813 9.288 ;
     RECT  30.913 40.656 31.82 40.68 ;
     RECT  31.633 42 31.82 43.608 ;
     RECT  31.165 15.408 31.861 17.064 ;
     RECT  29.704 18.144 31.861 18.168 ;
     RECT  31.861 15.408 31.957 18.168 ;
     RECT  29.704 3.408 32.108 3.432 ;
     RECT  31.813 5.136 32.108 9.384 ;
     RECT  31.1 10.56 32.108 14.232 ;
     RECT  31.957 15.408 32.108 18.552 ;
     RECT  31.777 19.824 32.108 33.624 ;
     RECT  31.309 34.752 32.108 34.776 ;
     RECT  32.029 36 32.108 36.024 ;
     RECT  31.697 37.008 32.108 38.184 ;
     RECT  31.949 39.312 32.108 39.336 ;
     RECT  31.82 40.656 32.108 43.608 ;
     RECT  32.108 2.148 32.212 44.292 ;
     RECT  32.212 2.418 32.404 44.022 ;
     RECT  32.404 3.408 32.609 4.008 ;
     RECT  32.404 8.784 32.753 10.104 ;
     RECT  32.404 19.824 32.969 34.2 ;
     RECT  32.404 11.232 33.149 18.6 ;
     RECT  33.149 11.232 33.155 15.48 ;
     RECT  32.404 40.56 33.155 43.848 ;
     RECT  32.969 19.824 33.365 34.152 ;
     RECT  33.365 25.536 33.395 34.152 ;
     RECT  33.155 40.56 33.445 40.68 ;
     RECT  32.404 35.28 33.491 39.336 ;
     RECT  32.753 8.784 33.505 9.816 ;
     RECT  33.491 35.28 33.545 39.288 ;
     RECT  33.155 41.664 33.613 43.848 ;
     RECT  33.149 16.56 33.644 18.6 ;
     RECT  33.365 19.824 33.644 24.504 ;
     RECT  32.404 5.232 33.685 6.12 ;
     RECT  32.404 7.44 33.685 7.464 ;
     RECT  33.644 16.56 33.731 24.504 ;
     RECT  33.545 35.328 33.772 38.712 ;
     RECT  33.505 8.544 33.793 9.816 ;
     RECT  33.155 11.232 33.793 14.28 ;
     RECT  33.613 2.88 33.925 2.904 ;
     RECT  32.609 3.984 33.925 4.008 ;
     RECT  33.685 5.232 33.937 7.464 ;
     RECT  33.155 15.456 34.117 15.48 ;
     RECT  33.731 16.56 34.117 18.264 ;
     RECT  33.925 2.88 34.549 4.008 ;
     RECT  33.793 8.544 34.652 14.28 ;
     RECT  34.117 15.456 34.652 18.264 ;
     RECT  33.395 25.536 34.765 33.864 ;
     RECT  33.445 40.416 34.765 40.68 ;
     RECT  33.613 41.664 34.765 44.088 ;
     RECT  34.549 2.784 34.808 4.008 ;
     RECT  33.937 5.04 34.808 7.464 ;
     RECT  34.652 8.544 34.808 18.264 ;
     RECT  33.731 19.824 34.808 24.504 ;
     RECT  34.765 25.536 34.808 34.152 ;
     RECT  33.772 35.328 34.808 37.56 ;
     RECT  33.772 38.688 34.808 38.712 ;
     RECT  34.765 40.416 34.808 44.088 ;
     RECT  34.808 2.148 34.912 44.292 ;
     RECT  34.912 2.256 35.104 44.088 ;
     RECT  35.104 7.104 35.165 13.656 ;
     RECT  35.104 35.328 35.165 37.608 ;
     RECT  35.104 15.84 35.201 18.264 ;
     RECT  35.201 15.84 35.237 18.168 ;
     RECT  35.165 35.328 35.345 37.512 ;
     RECT  35.165 7.104 35.489 13.608 ;
     RECT  35.104 41.136 35.489 44.088 ;
     RECT  35.104 14.832 35.525 14.856 ;
     RECT  35.104 2.256 35.705 4.296 ;
     RECT  35.705 2.784 35.741 4.296 ;
     RECT  35.345 35.328 35.929 37.176 ;
     RECT  35.104 25.104 36.029 33.864 ;
     RECT  35.237 16.032 36.101 18.168 ;
     RECT  35.104 19.824 36.133 23.64 ;
     RECT  35.104 5.52 36.169 6.12 ;
     RECT  35.741 2.832 36.209 4.296 ;
     RECT  35.489 12.768 36.241 13.608 ;
     RECT  36.029 25.536 36.389 33.864 ;
     RECT  36.169 5.424 36.457 6.12 ;
     RECT  35.489 7.104 36.457 11.496 ;
     RECT  35.104 39.888 36.457 39.912 ;
     RECT  35.104 38.688 36.709 38.712 ;
     RECT  36.457 39.888 36.709 40.152 ;
     RECT  36.457 4.656 36.86 11.496 ;
     RECT  36.241 12.768 36.86 13.656 ;
     RECT  36.101 16.032 36.925 17.64 ;
     RECT  36.86 4.656 36.997 13.656 ;
     RECT  36.997 4.656 37.141 13.896 ;
     RECT  36.781 34.752 37.177 34.776 ;
     RECT  35.929 35.952 37.177 37.176 ;
     RECT  36.389 25.536 37.285 33.384 ;
     RECT  37.285 25.056 37.321 33.384 ;
     RECT  37.321 24.912 37.357 33.384 ;
     RECT  36.209 2.832 37.508 3.432 ;
     RECT  37.141 4.656 37.508 14.28 ;
     RECT  36.925 15.264 37.508 17.64 ;
     RECT  36.133 19.824 37.508 23.928 ;
     RECT  37.357 24.912 37.508 33.624 ;
     RECT  37.177 34.752 37.508 37.176 ;
     RECT  36.709 38.688 37.508 40.152 ;
     RECT  35.489 41.472 37.508 44.088 ;
     RECT  37.508 2.148 37.612 44.292 ;
     RECT  37.612 2.418 37.804 44.022 ;
     RECT  37.804 4.416 37.865 7.464 ;
     RECT  37.804 23.328 38.045 33.624 ;
     RECT  37.804 8.784 38.051 17.352 ;
     RECT  37.865 4.752 38.081 7.464 ;
     RECT  38.045 23.328 38.081 33.048 ;
     RECT  37.804 35.424 38.153 40.104 ;
     RECT  38.153 35.424 38.195 36.504 ;
     RECT  38.051 11.472 38.477 17.352 ;
     RECT  38.195 35.424 38.797 36.024 ;
     RECT  38.477 15.024 38.821 17.352 ;
     RECT  38.821 15.024 38.833 18.168 ;
     RECT  37.804 19.344 38.833 22.344 ;
     RECT  37.804 42 38.833 42.024 ;
     RECT  38.051 8.784 38.837 10.104 ;
     RECT  38.153 37.92 38.837 40.104 ;
     RECT  38.833 15.024 38.867 22.344 ;
     RECT  38.837 8.784 38.941 9.816 ;
     RECT  38.833 42 38.945 42.12 ;
     RECT  38.837 37.92 39.053 40.056 ;
     RECT  38.081 7.44 39.085 7.464 ;
     RECT  38.941 8.64 39.085 9.816 ;
     RECT  37.804 2.832 39.157 3.432 ;
     RECT  38.081 4.752 39.26 6.12 ;
     RECT  39.085 7.44 39.26 9.816 ;
     RECT  38.477 11.472 39.5 13.992 ;
     RECT  38.797 34.992 39.517 36.024 ;
     RECT  39.481 33.888 39.553 33.912 ;
     RECT  39.517 34.992 39.553 36.696 ;
     RECT  37.804 43.872 39.553 43.896 ;
     RECT  39.553 33.888 39.769 36.696 ;
     RECT  39.053 37.92 39.769 39.336 ;
     RECT  39.553 43.344 39.805 43.896 ;
     RECT  39.157 2.832 39.836 3.72 ;
     RECT  39.769 33.888 39.841 39.336 ;
     RECT  39.836 2.544 39.877 3.72 ;
     RECT  39.26 4.752 39.877 9.816 ;
     RECT  38.081 23.328 39.877 32.52 ;
     RECT  39.841 33.648 39.877 39.336 ;
     RECT  38.945 42 39.925 42.024 ;
     RECT  39.805 43.344 39.925 43.944 ;
     RECT  38.867 15.984 40.021 22.344 ;
     RECT  39.877 23.328 40.021 39.336 ;
     RECT  39.925 41.184 40.049 43.944 ;
     RECT  39.877 2.544 40.208 9.816 ;
     RECT  39.5 11.376 40.208 13.992 ;
     RECT  40.021 15.984 40.208 39.336 ;
     RECT  40.049 41.088 40.208 43.944 ;
     RECT  40.208 2.148 40.312 44.292 ;
     RECT  40.312 2.256 40.504 44.022 ;
     RECT  40.504 11.472 40.601 36.36 ;
     RECT  40.504 42.24 40.643 43.944 ;
     RECT  40.601 11.472 40.645 32.52 ;
     RECT  40.504 37.44 40.691 37.464 ;
     RECT  40.645 28.704 40.709 32.52 ;
     RECT  40.504 3.264 40.817 9.672 ;
     RECT  40.504 38.688 40.817 38.712 ;
     RECT  40.643 42.24 40.853 42.6 ;
     RECT  40.601 33.648 40.997 35.88 ;
     RECT  40.645 11.472 41.027 27.72 ;
     RECT  40.997 33.936 41.069 35.88 ;
     RECT  40.504 39.984 41.141 40.584 ;
     RECT  40.853 42.24 41.141 42.264 ;
     RECT  41.027 11.472 41.249 17.64 ;
     RECT  40.504 2.256 41.459 2.28 ;
     RECT  40.817 3.264 41.459 9.528 ;
     RECT  41.249 11.472 41.605 17.112 ;
     RECT  40.709 28.704 41.645 32.28 ;
     RECT  41.027 19.152 41.933 27.72 ;
     RECT  41.645 29.04 42.001 32.28 ;
     RECT  41.933 19.152 42.037 24.504 ;
     RECT  41.459 3.6 42.073 9.528 ;
     RECT  41.933 25.536 42.325 27.72 ;
     RECT  41.141 39.984 42.757 40.488 ;
     RECT  42.073 3.6 42.908 9.624 ;
     RECT  41.605 10.992 42.908 17.112 ;
     RECT  42.037 18.48 42.908 24.504 ;
     RECT  42.325 25.536 42.908 27.912 ;
     RECT  42.001 29.04 42.908 32.328 ;
     RECT  41.069 33.936 42.908 34.488 ;
     RECT  42.001 35.904 42.908 35.928 ;
     RECT  42.577 37.008 42.908 37.032 ;
     RECT  42.109 38.064 42.908 38.088 ;
     RECT  42.757 39.888 42.908 40.488 ;
     RECT  42.908 2.148 43.012 44.292 ;
     RECT  43.012 2.418 43.204 44.022 ;
     RECT  43.204 19.92 43.265 24.504 ;
     RECT  43.204 11.472 43.337 13.848 ;
     RECT  43.204 27.84 43.337 33.384 ;
     RECT  43.204 37.056 43.337 37.08 ;
     RECT  43.337 11.472 43.373 11.928 ;
     RECT  43.204 7.392 43.445 7.464 ;
     RECT  43.337 27.84 43.445 33.288 ;
     RECT  43.445 27.84 43.517 32.328 ;
     RECT  43.337 12.912 43.571 13.848 ;
     RECT  43.204 15.216 43.612 15.24 ;
     RECT  43.204 26.64 43.619 26.664 ;
     RECT  43.517 27.84 43.619 31.944 ;
     RECT  43.619 28.368 44.165 31.944 ;
     RECT  43.265 19.92 45.313 24.36 ;
     RECT  43.571 12.912 45.601 13.512 ;
     RECT  45.313 19.92 45.601 24.456 ;
     RECT  43.204 25.536 45.601 25.56 ;
     RECT  44.165 29.136 45.637 31.944 ;
     RECT  43.373 11.472 45.673 11.496 ;
     RECT  45.601 12.816 45.673 13.512 ;
     RECT  45.637 29.136 45.673 32.04 ;
     RECT  45.673 11.472 45.709 13.608 ;
     RECT  45.709 11.472 45.997 13.704 ;
     RECT  45.997 11.472 46.069 13.992 ;
     RECT  43.204 8.784 46.109 8.808 ;
     RECT  43.445 7.44 46.181 7.464 ;
     RECT  43.204 6.096 46.325 6.12 ;
     RECT  43.204 16.56 46.325 16.584 ;
     RECT  46.069 11.472 46.361 14.088 ;
     RECT  46.361 12.24 46.38 14.088 ;
     RECT  45.601 19.92 46.38 25.992 ;
     RECT  45.673 29.136 46.38 32.136 ;
    LAYER M5 ;
     RECT  2.4 2.137 2.52 2.151 ;
     RECT  5.1 2.137 5.22 2.151 ;
     RECT  7.8 2.137 7.92 2.151 ;
     RECT  10.5 2.137 10.62 2.151 ;
     RECT  13.2 2.137 13.32 2.151 ;
     RECT  15.9 2.137 16.02 2.151 ;
     RECT  18.6 2.137 18.72 2.151 ;
     RECT  21.3 2.137 21.42 2.151 ;
     RECT  24 2.137 24.12 2.151 ;
     RECT  26.7 2.137 26.82 2.151 ;
     RECT  29.4 2.137 29.52 2.151 ;
     RECT  32.1 2.137 32.22 2.151 ;
     RECT  34.8 2.137 34.92 2.151 ;
     RECT  37.5 2.137 37.62 2.151 ;
     RECT  40.2 2.137 40.32 2.151 ;
     RECT  42.9 2.137 43.02 2.151 ;
     RECT  5.1 2.151 5.412 2.245 ;
     RECT  13.2 2.151 13.512 2.245 ;
     RECT  15.9 2.151 16.212 2.245 ;
     RECT  21.3 2.151 21.612 2.245 ;
     RECT  29.4 2.151 29.712 2.245 ;
     RECT  34.8 2.151 35.112 2.245 ;
     RECT  40.2 2.151 40.512 2.245 ;
     RECT  26.7 2.151 27.012 2.533 ;
     RECT  40.2 2.245 41.448 2.533 ;
     RECT  21.3 2.245 21.72 2.725 ;
     RECT  10.5 2.151 10.812 2.821 ;
     RECT  24 2.151 24.312 2.821 ;
     RECT  39.888 2.533 41.448 2.821 ;
     RECT  4.896 2.245 5.412 2.915 ;
     RECT  23.904 2.821 24.312 3.155 ;
     RECT  34.8 2.245 35.256 3.157 ;
     RECT  29.4 2.245 29.88 3.443 ;
     RECT  33.936 3.157 35.256 3.443 ;
     RECT  26.592 2.533 27.012 3.539 ;
     RECT  39.312 2.821 41.448 3.589 ;
     RECT  42.9 2.151 43.212 3.589 ;
     RECT  26.7 3.539 27.012 3.685 ;
     RECT  33.936 3.443 35.112 4.019 ;
     RECT  20.88 2.725 21.72 4.115 ;
     RECT  39.312 3.589 43.212 4.355 ;
     RECT  7.8 2.151 8.112 4.501 ;
     RECT  15.9 2.245 16.344 4.501 ;
     RECT  10.5 2.821 11.688 4.547 ;
     RECT  13.2 2.245 13.608 4.547 ;
     RECT  18.6 2.151 18.912 4.645 ;
     RECT  20.88 4.115 21.612 4.691 ;
     RECT  2.4 2.151 2.712 4.837 ;
     RECT  3.792 3.397 3.816 4.837 ;
     RECT  26.7 3.685 27.96 4.837 ;
     RECT  2.4 4.837 3.816 4.883 ;
     RECT  42.144 4.355 43.212 4.979 ;
     RECT  26.7 4.837 28.296 5.029 ;
     RECT  29.4 3.443 29.712 5.029 ;
     RECT  6.912 4.501 8.112 5.077 ;
     RECT  15.9 4.501 17.112 5.123 ;
     RECT  24 3.155 24.312 5.269 ;
     RECT  25.536 4.213 25.56 5.269 ;
     RECT  10.5 4.547 11.448 5.459 ;
     RECT  13.2 4.547 13.512 5.605 ;
     RECT  39.312 4.355 40.512 5.605 ;
     RECT  21.3 4.691 21.612 5.653 ;
     RECT  13.104 5.605 13.512 5.701 ;
     RECT  15.9 5.123 16.344 5.701 ;
     RECT  26.7 5.029 29.712 5.797 ;
     RECT  2.4 4.883 2.856 5.891 ;
     RECT  34.8 4.019 35.112 5.893 ;
     RECT  15.072 5.701 16.344 6.035 ;
     RECT  32.1 2.151 32.412 6.037 ;
     RECT  37.5 2.151 37.812 6.613 ;
     RECT  24 5.269 25.56 6.707 ;
     RECT  6.864 5.077 8.112 6.851 ;
     RECT  41.616 6.229 41.64 7.045 ;
     RECT  42.9 4.979 43.212 7.045 ;
     RECT  41.616 7.045 43.212 7.091 ;
     RECT  20.544 5.653 21.612 7.381 ;
     RECT  26.592 5.797 29.712 7.381 ;
     RECT  24 6.707 24.6 7.427 ;
     RECT  25.632 7.381 29.712 7.427 ;
     RECT  7.2 6.851 8.112 7.475 ;
     RECT  20.544 7.381 21.72 7.571 ;
     RECT  20.736 7.571 21.72 7.619 ;
     RECT  25.632 7.427 27.912 7.667 ;
     RECT  22.848 7.573 22.872 7.763 ;
     RECT  20.976 7.619 21.72 7.861 ;
     RECT  18.6 4.645 19.176 7.909 ;
     RECT  13.104 5.701 13.848 7.957 ;
     RECT  18.48 7.909 19.176 8.051 ;
     RECT  31.44 6.037 32.412 8.147 ;
     RECT  10.5 5.459 10.812 8.245 ;
     RECT  15.792 6.035 16.344 8.531 ;
     RECT  7.68 7.475 8.112 8.533 ;
     RECT  24 7.427 24.312 8.533 ;
     RECT  34.224 5.893 35.112 8.579 ;
     RECT  39.072 5.605 40.512 8.675 ;
     RECT  36.096 7.093 36.12 8.723 ;
     RECT  2.4 5.891 2.712 8.725 ;
     RECT  26.592 7.667 27.912 8.821 ;
     RECT  31.488 8.147 32.412 9.061 ;
     RECT  37.392 6.613 37.812 9.061 ;
     RECT  39.072 8.675 39.144 9.061 ;
     RECT  31.488 9.061 33.336 9.109 ;
     RECT  6.864 8.533 8.112 9.155 ;
     RECT  20.976 7.861 21.768 9.205 ;
     RECT  26.592 8.821 27.96 9.251 ;
     RECT  37.392 9.061 39.144 9.301 ;
     RECT  20.976 9.205 22.008 9.349 ;
     RECT  12.672 7.957 13.848 9.491 ;
     RECT  42.096 7.091 43.212 9.491 ;
     RECT  12.672 9.491 13.512 9.493 ;
     RECT  36.48 9.301 39.144 9.539 ;
     RECT  31.152 9.109 33.336 9.637 ;
     RECT  20.976 9.349 22.2 9.781 ;
     RECT  24 8.533 24.504 9.781 ;
     RECT  29.4 7.427 29.712 9.925 ;
     RECT  2.4 8.725 3.528 10.067 ;
     RECT  15.792 8.531 16.212 10.067 ;
     RECT  26.7 9.251 27.96 10.115 ;
     RECT  36.912 9.539 39.144 10.115 ;
     RECT  20.976 9.781 24.504 10.211 ;
     RECT  31.152 9.637 33.528 10.595 ;
     RECT  26.7 10.115 27.576 10.597 ;
     RECT  21.072 10.211 24.504 10.787 ;
     RECT  18.6 8.051 19.176 10.883 ;
     RECT  15.9 10.067 16.212 10.885 ;
     RECT  21.12 10.787 24.504 10.931 ;
     RECT  12.288 9.493 13.512 11.125 ;
     RECT  2.4 10.067 2.712 11.365 ;
     RECT  39.12 10.115 39.144 11.365 ;
     RECT  40.2 8.675 40.512 11.365 ;
     RECT  2.4 11.365 2.856 11.507 ;
     RECT  29.4 9.925 29.88 11.605 ;
     RECT  7.536 9.155 8.112 11.651 ;
     RECT  36.912 10.115 38.04 11.699 ;
     RECT  25.728 10.597 27.576 11.747 ;
     RECT  39.12 11.365 40.512 11.795 ;
     RECT  7.68 11.651 8.112 11.891 ;
     RECT  29.088 11.605 29.88 11.891 ;
     RECT  36.912 11.699 37.944 11.939 ;
     RECT  9.12 11.365 9.144 11.941 ;
     RECT  10.272 8.245 10.812 11.941 ;
     RECT  29.4 11.891 29.88 11.987 ;
     RECT  39.552 11.795 40.512 12.035 ;
     RECT  12.288 11.125 13.656 12.275 ;
     RECT  21.12 10.931 24.312 12.275 ;
     RECT  18.6 10.883 18.912 12.325 ;
     RECT  9.12 11.941 10.812 12.467 ;
     RECT  15.9 10.885 16.344 12.467 ;
     RECT  7.8 11.891 8.112 12.517 ;
     RECT  9.12 12.467 9.24 12.517 ;
     RECT  41.904 11.749 41.928 12.517 ;
     RECT  42.9 9.491 43.212 12.517 ;
     RECT  32.1 10.595 33.528 12.563 ;
     RECT  25.728 11.747 27.012 12.853 ;
     RECT  34.8 8.579 35.112 12.901 ;
     RECT  25.344 12.853 27.144 12.995 ;
     RECT  10.272 12.467 10.812 12.997 ;
     RECT  7.8 12.517 9.24 13.043 ;
     RECT  37.152 11.939 37.812 13.045 ;
     RECT  6.624 12.325 6.648 13.091 ;
     RECT  7.8 13.043 9.144 13.139 ;
     RECT  13.104 12.275 13.656 13.139 ;
     RECT  28.368 12.517 28.392 13.189 ;
     RECT  29.4 11.987 29.712 13.189 ;
     RECT  13.104 13.139 13.608 13.285 ;
     RECT  13.056 13.285 13.608 13.379 ;
     RECT  25.344 12.995 25.368 13.379 ;
     RECT  28.368 13.189 29.712 13.427 ;
     RECT  41.904 12.517 43.212 13.523 ;
     RECT  23.328 12.275 24.312 13.571 ;
     RECT  14.784 9.589 14.808 13.573 ;
     RECT  15.9 12.467 16.212 13.573 ;
     RECT  23.376 13.571 24.312 13.667 ;
     RECT  28.368 13.427 28.392 13.715 ;
     RECT  42.9 13.523 43.212 13.813 ;
     RECT  41.904 13.523 41.928 13.859 ;
     RECT  24 13.667 24.312 13.909 ;
     RECT  21.12 12.275 22.2 14.099 ;
     RECT  10.272 12.997 11.592 14.149 ;
     RECT  32.1 12.563 32.808 14.197 ;
     RECT  40.2 12.035 40.512 14.197 ;
     RECT  31.776 14.197 32.808 14.245 ;
     RECT  37.152 13.045 38.232 14.291 ;
     RECT  17.184 13.141 17.208 14.339 ;
     RECT  21.12 14.099 21.612 14.339 ;
     RECT  26.544 12.995 27.144 14.483 ;
     RECT  5.1 2.915 5.412 14.485 ;
     RECT  7.8 13.139 8.112 14.485 ;
     RECT  9.12 13.139 9.144 14.485 ;
     RECT  34.8 12.901 35.352 14.485 ;
     RECT  31.776 14.245 33.144 14.675 ;
     RECT  14.784 13.573 16.212 14.677 ;
     RECT  26.544 14.483 27.012 14.773 ;
     RECT  34.704 14.485 35.352 14.867 ;
     RECT  24 13.909 24.456 14.917 ;
     RECT  25.92 14.773 27.012 14.917 ;
     RECT  30.768 13.957 30.792 14.963 ;
     RECT  13.056 13.379 13.512 15.011 ;
     RECT  40.2 14.197 40.632 15.061 ;
     RECT  42.9 13.813 43.56 15.061 ;
     RECT  7.8 14.485 9.144 15.205 ;
     RECT  42.288 15.061 43.56 15.251 ;
     RECT  29.4 13.427 29.712 15.253 ;
     RECT  6.864 15.205 9.144 15.349 ;
     RECT  37.5 14.291 37.812 15.349 ;
     RECT  38.832 15.013 38.856 15.349 ;
     RECT  31.776 14.675 33.048 15.443 ;
     RECT  4.56 14.485 5.412 15.491 ;
     RECT  6.384 15.349 9.144 15.491 ;
     RECT  24 14.917 27.012 15.491 ;
     RECT  25.92 15.491 27.012 15.635 ;
     RECT  24 15.491 24.456 15.781 ;
     RECT  10.272 14.149 11.832 15.925 ;
     RECT  21.3 14.339 21.612 15.973 ;
     RECT  6.384 15.491 8.112 16.019 ;
     RECT  37.296 15.349 38.856 16.019 ;
     RECT  28.464 15.253 29.712 16.211 ;
     RECT  10.224 15.925 11.832 16.405 ;
     RECT  13.2 15.011 13.512 16.405 ;
     RECT  14.784 14.677 16.344 16.405 ;
     RECT  23.28 15.781 24.456 16.405 ;
     RECT  18.432 12.325 18.912 16.499 ;
     RECT  6.864 16.019 8.112 16.501 ;
     RECT  9.12 15.491 9.144 16.501 ;
     RECT  10.224 16.405 12.072 16.501 ;
     RECT  22.848 16.405 24.456 16.501 ;
     RECT  34.704 14.867 35.112 16.501 ;
     RECT  13.2 16.405 16.344 16.595 ;
     RECT  18.48 16.499 18.912 16.595 ;
     RECT  6.864 16.501 12.072 16.835 ;
     RECT  26.7 15.635 27.012 16.837 ;
     RECT  22.848 16.501 25.368 16.883 ;
     RECT  3.936 16.789 3.96 16.931 ;
     RECT  21.12 15.973 21.612 16.981 ;
     RECT  28.512 16.211 29.712 17.027 ;
     RECT  26.496 16.837 27.012 17.029 ;
     RECT  21.024 16.981 21.612 17.123 ;
     RECT  29.04 17.027 29.712 17.123 ;
     RECT  42.288 15.251 43.212 17.123 ;
     RECT  34.176 16.501 35.112 17.171 ;
     RECT  31.968 15.443 33.048 17.365 ;
     RECT  40.2 15.061 40.728 17.605 ;
     RECT  6.864 16.835 11.832 17.651 ;
     RECT  34.704 17.171 35.112 17.651 ;
     RECT  37.296 16.019 37.812 17.651 ;
     RECT  13.2 16.595 16.212 18.037 ;
     RECT  5.1 15.491 5.412 18.133 ;
     RECT  13.104 18.037 16.212 18.179 ;
     RECT  31.872 17.365 33.048 18.179 ;
     RECT  38.832 16.019 38.856 18.179 ;
     RECT  18.6 16.595 18.912 18.181 ;
     RECT  7.104 17.651 11.832 18.275 ;
     RECT  26.16 17.029 27.012 18.419 ;
     RECT  31.968 18.179 33.048 18.565 ;
     RECT  22.848 16.883 24.456 18.659 ;
     RECT  42.9 17.123 43.212 18.709 ;
     RECT  22.848 18.659 24.408 18.755 ;
     RECT  2.4 11.507 2.712 18.757 ;
     RECT  21.12 17.123 21.612 18.757 ;
     RECT  40.2 17.605 41.016 18.757 ;
     RECT  2.4 18.757 2.808 19.093 ;
     RECT  39.312 18.757 41.016 19.187 ;
     RECT  42.144 18.709 43.212 19.187 ;
     RECT  15.9 18.179 16.212 19.333 ;
     RECT  10.272 18.275 11.832 19.427 ;
     RECT  20.496 18.757 21.612 19.427 ;
     RECT  39.312 19.187 40.728 19.523 ;
     RECT  11.808 19.427 11.832 19.811 ;
     RECT  28.032 18.181 28.056 19.811 ;
     RECT  23.088 18.755 24.408 20.003 ;
     RECT  40.2 19.523 40.728 20.003 ;
     RECT  13.104 18.179 14.904 20.051 ;
     RECT  24 20.003 24.408 20.051 ;
     RECT  18.6 18.181 19.032 20.149 ;
     RECT  31.968 18.565 33.72 20.387 ;
     RECT  10.272 19.427 10.812 20.437 ;
     RECT  2.4 19.093 3.096 20.579 ;
     RECT  7.104 18.275 8.76 20.579 ;
     RECT  5.1 18.133 5.544 20.581 ;
     RECT  13.2 20.051 14.904 20.627 ;
     RECT  2.4 20.579 2.808 20.675 ;
     RECT  13.2 20.627 14.808 20.675 ;
     RECT  18.6 20.149 19.368 20.725 ;
     RECT  29.4 17.123 29.712 20.773 ;
     RECT  29.232 20.773 29.712 20.869 ;
     RECT  15.9 19.333 17.016 21.061 ;
     RECT  4.992 20.581 5.544 21.107 ;
     RECT  5.1 21.107 5.544 21.155 ;
     RECT  7.104 20.579 8.112 21.155 ;
     RECT  18.6 20.725 20.136 21.155 ;
     RECT  14.688 20.675 14.808 21.203 ;
     RECT  15.9 21.061 17.112 21.203 ;
     RECT  13.2 20.675 13.512 21.397 ;
     RECT  26.352 18.419 27.012 21.397 ;
     RECT  46.128 21.157 46.152 21.539 ;
     RECT  13.104 21.397 13.512 21.635 ;
     RECT  21.12 19.427 21.612 21.635 ;
     RECT  2.4 20.675 2.712 21.637 ;
     RECT  40.2 20.003 40.512 21.733 ;
     RECT  29.184 20.869 29.712 21.781 ;
     RECT  34.8 17.651 35.112 21.829 ;
     RECT  10.272 20.437 11.448 21.971 ;
     RECT  10.272 21.971 10.812 21.973 ;
     RECT  26.352 21.397 27.864 22.067 ;
     RECT  29.136 21.781 29.712 22.067 ;
     RECT  31.968 20.387 32.808 22.067 ;
     RECT  40.032 21.733 40.512 22.069 ;
     RECT  24 20.051 24.312 22.165 ;
     RECT  18.6 21.155 19.368 22.259 ;
     RECT  34.8 21.829 35.832 22.259 ;
     RECT  9.648 21.973 10.812 22.741 ;
     RECT  2.4 21.637 3.48 22.787 ;
     RECT  17.472 21.493 17.496 22.885 ;
     RECT  18.6 22.259 19.032 22.885 ;
     RECT  21.3 21.635 21.612 22.981 ;
     RECT  24 22.165 25.128 23.075 ;
     RECT  26.352 22.067 27.012 23.269 ;
     RECT  7.344 21.155 8.112 23.317 ;
     RECT  40.032 22.069 41.064 23.411 ;
     RECT  21.168 22.981 21.612 23.413 ;
     RECT  13.2 21.635 13.512 23.461 ;
     RECT  14.784 21.203 14.808 23.461 ;
     RECT  15.9 21.203 16.212 23.461 ;
     RECT  24 23.075 25.08 23.555 ;
     RECT  20.352 23.413 21.612 23.699 ;
     RECT  13.2 23.461 14.808 23.701 ;
     RECT  15.792 23.461 16.212 23.701 ;
     RECT  17.472 22.885 19.032 23.747 ;
     RECT  13.2 23.701 16.212 23.891 ;
     RECT  9.6 22.741 10.812 23.893 ;
     RECT  21.12 23.699 21.612 23.893 ;
     RECT  37.5 17.651 37.812 23.893 ;
     RECT  26.352 23.269 27.48 23.987 ;
     RECT  26.4 23.987 27.48 24.131 ;
     RECT  40.032 23.411 40.512 24.181 ;
     RECT  0.144 24.181 0.168 24.467 ;
     RECT  41.76 23.941 41.784 24.515 ;
     RECT  13.2 23.891 14.904 24.563 ;
     RECT  13.2 24.563 14.376 24.661 ;
     RECT  21.12 23.893 22.104 24.661 ;
     RECT  7.344 23.317 8.232 24.709 ;
     RECT  13.104 24.661 14.376 24.803 ;
     RECT  37.5 23.893 38.136 24.947 ;
     RECT  7.344 24.709 8.28 25.043 ;
     RECT  37.5 24.947 37.812 25.045 ;
     RECT  15.9 23.891 16.212 25.189 ;
     RECT  17.472 23.747 18.912 25.189 ;
     RECT  21.12 24.661 22.296 25.189 ;
     RECT  26.4 24.131 27.012 25.285 ;
     RECT  21.072 25.189 22.296 25.619 ;
     RECT  29.4 22.067 29.712 25.621 ;
     RECT  5.1 21.155 5.412 25.669 ;
     RECT  32.1 22.067 32.808 25.717 ;
     RECT  4.368 25.669 5.412 26.197 ;
     RECT  13.2 24.803 14.376 26.197 ;
     RECT  3.936 26.197 5.412 26.243 ;
     RECT  7.344 25.043 8.112 26.243 ;
     RECT  15.9 25.189 18.912 26.243 ;
     RECT  30.816 25.717 32.808 26.243 ;
     RECT  37.296 25.045 37.812 26.243 ;
     RECT  17.472 26.243 18.912 26.293 ;
     RECT  17.472 26.293 19.128 26.483 ;
     RECT  28.8 25.621 29.712 26.581 ;
     RECT  42.9 19.187 43.212 26.629 ;
     RECT  34.8 22.259 35.112 26.725 ;
     RECT  13.104 26.197 14.376 26.819 ;
     RECT  26.4 25.285 27.288 26.917 ;
     RECT  39.888 24.181 40.512 26.917 ;
     RECT  31.296 26.243 32.808 27.203 ;
     RECT  21.12 25.619 22.296 27.301 ;
     RECT  39.888 26.917 40.632 27.349 ;
     RECT  3.936 26.243 3.96 27.395 ;
     RECT  28.8 26.581 30.312 27.395 ;
     RECT  15.9 26.243 16.212 27.829 ;
     RECT  17.472 26.483 18.912 27.829 ;
     RECT  42.9 26.629 43.608 28.403 ;
     RECT  28.8 27.395 29.712 28.405 ;
     RECT  32.1 27.203 32.808 28.405 ;
     RECT  26.4 26.917 27.624 28.547 ;
     RECT  39.216 27.349 40.632 28.693 ;
     RECT  21.12 27.301 22.776 28.837 ;
     RECT  39.216 28.693 41.16 29.123 ;
     RECT  28.656 28.405 29.712 29.267 ;
     RECT  37.5 26.243 37.812 29.317 ;
     RECT  42.9 28.403 43.212 29.413 ;
     RECT  37.5 29.317 37.992 29.461 ;
     RECT  39.216 29.123 40.512 29.461 ;
     RECT  21.024 28.837 22.776 29.507 ;
     RECT  5.1 26.243 5.412 29.605 ;
     RECT  21.072 29.507 22.776 29.699 ;
     RECT  34.8 26.725 35.4 29.699 ;
     RECT  32.1 28.405 33.192 29.747 ;
     RECT  13.2 26.819 14.376 29.749 ;
     RECT  15.9 27.829 18.912 29.749 ;
     RECT  7.8 26.243 8.112 29.845 ;
     RECT  13.2 29.749 18.912 29.845 ;
     RECT  37.392 29.461 40.512 29.939 ;
     RECT  13.2 29.845 19.224 30.083 ;
     RECT  42.9 29.413 43.32 30.179 ;
     RECT  34.8 29.699 35.112 30.181 ;
     RECT  11.952 28.501 11.976 30.275 ;
     RECT  21.12 29.699 22.776 30.323 ;
     RECT  26.4 28.547 27.144 30.371 ;
     RECT  9.504 23.893 10.812 30.373 ;
     RECT  9.168 30.373 10.812 30.419 ;
     RECT  4.464 29.605 5.412 30.469 ;
     RECT  42.9 30.179 43.212 30.757 ;
     RECT  26.4 30.371 27.012 30.851 ;
     RECT  46.128 30.757 46.152 30.899 ;
     RECT  9.168 30.419 9.192 30.947 ;
     RECT  21.3 30.323 22.776 30.947 ;
     RECT  7.68 29.845 8.112 30.949 ;
     RECT  21.3 30.947 22.584 31.043 ;
     RECT  40.2 29.939 40.512 31.141 ;
     RECT  4.464 30.469 5.88 31.379 ;
     RECT  26.7 30.851 27.012 31.429 ;
     RECT  2.4 22.787 2.712 31.525 ;
     RECT  10.272 30.419 10.812 31.669 ;
     RECT  34.128 30.181 35.112 31.763 ;
     RECT  13.2 30.083 14.376 31.765 ;
     RECT  29.28 29.267 29.712 31.811 ;
     RECT  42.768 30.757 43.212 32.243 ;
     RECT  10.272 31.669 10.968 32.437 ;
     RECT  40.2 31.141 40.68 32.485 ;
     RECT  37.392 29.939 38.712 32.531 ;
     RECT  39.888 32.485 40.68 32.531 ;
     RECT  12.672 31.765 14.376 32.533 ;
     RECT  15.9 30.083 19.224 32.533 ;
     RECT  12.672 32.533 19.224 32.723 ;
     RECT  7.008 30.949 8.112 32.725 ;
     RECT  7.008 32.725 8.472 32.773 ;
     RECT  2.4 31.525 3.432 32.821 ;
     RECT  4.464 31.379 5.412 32.821 ;
     RECT  13.2 32.723 19.224 32.869 ;
     RECT  13.2 32.869 19.992 33.107 ;
     RECT  39.888 32.531 40.512 33.539 ;
     RECT  24 23.555 24.312 33.541 ;
     RECT  2.4 32.821 5.412 33.587 ;
     RECT  4.176 33.587 5.412 33.589 ;
     RECT  7.008 32.773 8.616 33.589 ;
     RECT  21.3 31.043 22.104 33.589 ;
     RECT  34.8 31.763 35.112 33.589 ;
     RECT  26.7 31.429 27.192 33.827 ;
     RECT  21.3 33.589 23.016 33.923 ;
     RECT  32.1 29.747 32.808 34.117 ;
     RECT  13.2 33.107 17.496 34.165 ;
     RECT  26.7 33.827 27.012 34.165 ;
     RECT  4.176 33.589 8.616 34.259 ;
     RECT  18.48 33.107 19.224 34.259 ;
     RECT  7.68 34.259 8.616 34.549 ;
     RECT  40.2 33.539 40.512 34.693 ;
     RECT  29.4 31.811 29.712 34.741 ;
     RECT  4.176 34.259 6.264 34.787 ;
     RECT  26.16 34.165 27.012 34.883 ;
     RECT  10.272 32.437 11.064 34.931 ;
     RECT  12.816 34.165 17.496 34.979 ;
     RECT  10.272 34.931 10.92 35.219 ;
     RECT  21.3 33.923 22.296 35.269 ;
     RECT  32.1 34.117 33.384 35.315 ;
     RECT  7.68 34.549 9.096 35.317 ;
     RECT  34.8 33.589 35.88 35.363 ;
     RECT  37.5 32.531 37.812 35.413 ;
     RECT  12.816 34.979 17.448 35.459 ;
     RECT  13.2 35.459 17.448 35.699 ;
     RECT  21.168 35.269 22.296 35.843 ;
     RECT  4.176 34.787 5.412 35.845 ;
     RECT  4.176 35.845 6.072 35.989 ;
     RECT  7.632 35.317 9.096 35.989 ;
     RECT  24 33.541 24.504 35.989 ;
     RECT  29.088 34.741 29.712 36.277 ;
     RECT  21.168 35.843 22.104 36.467 ;
     RECT  13.2 35.699 14.808 36.515 ;
     RECT  26.352 34.883 27.012 36.515 ;
     RECT  32.1 35.315 32.808 36.515 ;
     RECT  37.5 35.413 38.184 36.515 ;
     RECT  34.8 35.363 35.112 36.565 ;
     RECT  4.176 35.989 9.096 36.611 ;
     RECT  5.1 36.611 9.096 36.803 ;
     RECT  18.6 34.259 19.224 36.853 ;
     RECT  23.712 35.989 24.504 36.997 ;
     RECT  32.1 36.515 32.664 36.997 ;
     RECT  13.2 36.515 14.136 37.043 ;
     RECT  28.896 36.277 29.712 37.091 ;
     RECT  26.7 36.515 27.012 37.141 ;
     RECT  23.712 36.997 25.128 37.379 ;
     RECT  29.088 37.091 29.712 37.427 ;
     RECT  21.3 36.467 22.104 37.429 ;
     RECT  39.936 34.693 40.512 37.429 ;
     RECT  34.704 36.565 35.112 37.571 ;
     RECT  24 37.379 25.128 37.619 ;
     RECT  5.1 36.803 5.736 37.909 ;
     RECT  21.168 37.429 22.104 38.005 ;
     RECT  31.728 36.997 32.664 38.149 ;
     RECT  33.696 36.997 33.72 38.149 ;
     RECT  39.936 37.429 40.68 38.149 ;
     RECT  31.728 38.149 33.72 38.195 ;
     RECT  37.5 36.515 37.944 38.195 ;
     RECT  11.952 36.853 11.976 38.243 ;
     RECT  21.12 38.005 22.104 38.339 ;
     RECT  6.912 36.803 9.096 38.435 ;
     RECT  32.1 38.195 33.72 38.435 ;
     RECT  4.608 37.909 5.736 38.581 ;
     RECT  15.9 35.699 17.448 38.675 ;
     RECT  24 37.619 24.504 38.677 ;
     RECT  39.792 38.149 40.68 38.723 ;
     RECT  4.56 38.581 5.736 38.725 ;
     RECT  26.7 37.141 27.384 39.299 ;
     RECT  13.2 37.043 13.512 39.301 ;
     RECT  14.544 38.485 14.568 39.301 ;
     RECT  24 38.677 25.032 39.301 ;
     RECT  32.1 38.435 33.48 39.301 ;
     RECT  39.792 38.723 40.512 39.347 ;
     RECT  7.68 38.435 9.096 39.395 ;
     RECT  10.272 35.219 10.812 39.589 ;
     RECT  11.904 39.013 11.928 39.589 ;
     RECT  13.2 39.301 14.568 39.733 ;
     RECT  15.9 38.675 16.92 39.733 ;
     RECT  7.8 39.395 9.096 39.827 ;
     RECT  2.4 33.587 2.712 39.829 ;
     RECT  4.032 38.725 5.736 39.875 ;
     RECT  29.28 37.427 29.712 39.877 ;
     RECT  42.9 32.243 43.212 39.877 ;
     RECT  24 39.301 25.704 40.355 ;
     RECT  7.8 39.827 8.112 40.405 ;
     RECT  31.968 39.301 33.48 40.451 ;
     RECT  4.032 39.875 5.592 40.453 ;
     RECT  42.768 39.877 43.212 40.499 ;
     RECT  7.44 40.405 8.112 40.549 ;
     RECT  18.6 36.853 19.512 40.549 ;
     RECT  6.72 40.549 8.112 40.645 ;
     RECT  31.968 40.451 33.144 40.645 ;
     RECT  28.848 39.877 29.712 40.789 ;
     RECT  10.272 39.589 11.928 40.835 ;
     RECT  13.2 39.733 16.92 41.027 ;
     RECT  18.6 40.549 20.136 41.027 ;
     RECT  40.032 39.347 40.512 41.173 ;
     RECT  21.3 38.339 22.104 41.221 ;
     RECT  31.872 40.645 33.144 41.363 ;
     RECT  11.904 40.835 11.928 41.411 ;
     RECT  32.1 41.363 33.144 41.411 ;
     RECT  6.576 40.645 8.112 41.459 ;
     RECT  2.4 39.829 2.808 41.651 ;
     RECT  3.984 40.453 5.592 41.651 ;
     RECT  9.12 40.165 9.144 41.651 ;
     RECT  24 40.355 24.504 41.651 ;
     RECT  15.504 41.027 16.92 41.699 ;
     RECT  25.68 40.355 25.704 41.699 ;
     RECT  6.72 41.459 8.112 41.747 ;
     RECT  4.032 41.651 5.592 41.891 ;
     RECT  4.032 41.891 5.412 42.227 ;
     RECT  24 41.651 24.456 42.227 ;
     RECT  28.752 40.789 29.712 42.227 ;
     RECT  39.936 41.173 40.512 42.229 ;
     RECT  29.28 42.227 29.712 42.419 ;
     RECT  13.2 41.027 14.088 42.467 ;
     RECT  4.032 42.227 4.056 42.611 ;
     RECT  39.936 42.229 40.632 42.611 ;
     RECT  21.3 41.221 22.728 42.613 ;
     RECT  26.7 39.299 27.012 42.709 ;
     RECT  32.1 41.411 33.048 42.709 ;
     RECT  19.92 41.027 20.136 42.755 ;
     RECT  29.4 42.419 29.712 42.805 ;
     RECT  20.112 42.755 20.136 42.851 ;
     RECT  21.3 42.613 22.92 43.331 ;
     RECT  29.4 42.805 30.12 43.331 ;
     RECT  31.92 42.709 33.048 43.379 ;
     RECT  7.104 41.747 8.112 43.763 ;
     RECT  32.1 43.379 33.048 43.811 ;
     RECT  26.7 42.709 27.384 43.955 ;
     RECT  40.08 42.611 40.632 43.955 ;
     RECT  25.488 42.997 25.512 44.099 ;
     RECT  10.272 40.835 10.812 44.147 ;
     RECT  2.4 41.651 2.712 44.289 ;
     RECT  5.1 42.227 5.412 44.289 ;
     RECT  7.8 43.763 8.112 44.289 ;
     RECT  10.5 44.147 10.812 44.289 ;
     RECT  13.2 42.467 13.512 44.289 ;
     RECT  18.6 41.027 18.912 44.289 ;
     RECT  24 42.227 24.312 44.289 ;
     RECT  26.7 43.955 27.012 44.289 ;
     RECT  29.4 43.331 29.712 44.289 ;
     RECT  32.1 43.811 32.412 44.289 ;
     RECT  34.8 37.571 35.112 44.289 ;
     RECT  37.5 38.195 37.812 44.289 ;
     RECT  40.2 43.955 40.512 44.289 ;
     RECT  42.9 40.499 43.212 44.289 ;
     RECT  2.4 44.289 2.52 44.303 ;
     RECT  5.1 44.289 5.22 44.303 ;
     RECT  7.8 44.289 7.92 44.303 ;
     RECT  10.5 44.289 10.62 44.303 ;
     RECT  13.2 44.289 13.32 44.303 ;
     RECT  15.9 41.699 16.92 44.303 ;
     RECT  18.6 44.289 18.72 44.303 ;
     RECT  21.3 43.331 22.104 44.303 ;
     RECT  24 44.289 24.12 44.303 ;
     RECT  26.7 44.289 26.82 44.303 ;
     RECT  29.4 44.289 29.52 44.303 ;
     RECT  32.1 44.289 32.22 44.303 ;
     RECT  34.8 44.289 34.92 44.303 ;
     RECT  37.5 44.289 37.62 44.303 ;
     RECT  40.2 44.289 40.32 44.303 ;
     RECT  42.9 44.289 43.02 44.303 ;
     RECT  22.08 44.303 22.104 46.211 ;
     RECT  16.896 44.303 16.92 46.403 ;
  END
END qfd_landh0d8n_116_EW_46x46
END LIBRARY
